# Generated by FakeRAM 2.0 (routing-friendly)
VERSION 5.7 ;
BUSBITCHARS "[]" ;
PROPERTYDEFINITIONS
  MACRO width INTEGER ;
  MACRO depth INTEGER ;
  MACRO banks INTEGER ;
END PROPERTYDEFINITIONS
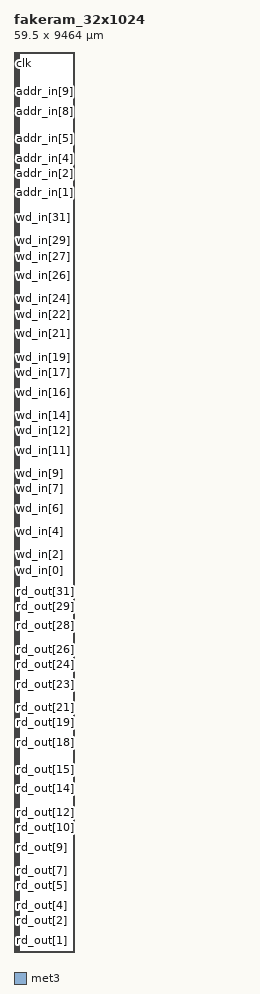
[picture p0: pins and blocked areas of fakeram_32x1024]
MACRO fakeram_32x1024
  PROPERTY width 32 ;
  PROPERTY depth 1024 ;
  PROPERTY banks 1 ;
  FOREIGN fakeram_32x1024 0 0 ;
  SYMMETRY X Y R90 ;
  SIZE 59.500 BY 9464.000 ;
  CLASS BLOCK ;
  PIN rd_out[0]
    DIRECTION OUTPUT ;
    USE SIGNAL ;
    PORT
      LAYER met3 ;
      RECT 1.000 0.680 3.000 1.380 ;
    END
    PORT
      LAYER met3 ;
      RECT 1.000 0.330 4.000 1.730 ;
    END
  END rd_out[0]
  PIN rd_out[1]
    DIRECTION OUTPUT ;
    USE SIGNAL ;
    PORT
      LAYER met3 ;
      RECT 1.000 123.080 3.000 123.780 ;
    END
    PORT
      LAYER met3 ;
      RECT 1.000 122.730 4.000 124.130 ;
    END
  END rd_out[1]
  PIN rd_out[2]
    DIRECTION OUTPUT ;
    USE SIGNAL ;
    PORT
      LAYER met3 ;
      RECT 1.000 245.480 3.000 246.180 ;
    END
    PORT
      LAYER met3 ;
      RECT 1.000 245.130 4.000 246.530 ;
    END
  END rd_out[2]
  PIN rd_out[3]
    DIRECTION OUTPUT ;
    USE SIGNAL ;
    PORT
      LAYER met3 ;
      RECT 1.000 367.880 3.000 368.580 ;
    END
    PORT
      LAYER met3 ;
      RECT 1.000 367.530 4.000 368.930 ;
    END
  END rd_out[3]
  PIN rd_out[4]
    DIRECTION OUTPUT ;
    USE SIGNAL ;
    PORT
      LAYER met3 ;
      RECT 1.000 490.280 3.000 490.980 ;
    END
    PORT
      LAYER met3 ;
      RECT 1.000 489.930 4.000 491.330 ;
    END
  END rd_out[4]
  PIN rd_out[5]
    DIRECTION OUTPUT ;
    USE SIGNAL ;
    PORT
      LAYER met3 ;
      RECT 1.000 612.680 3.000 613.380 ;
    END
    PORT
      LAYER met3 ;
      RECT 1.000 612.330 4.000 613.730 ;
    END
  END rd_out[5]
  PIN rd_out[6]
    DIRECTION OUTPUT ;
    USE SIGNAL ;
    PORT
      LAYER met3 ;
      RECT 1.000 735.080 3.000 735.780 ;
    END
    PORT
      LAYER met3 ;
      RECT 1.000 734.730 4.000 736.130 ;
    END
  END rd_out[6]
  PIN rd_out[7]
    DIRECTION OUTPUT ;
    USE SIGNAL ;
    PORT
      LAYER met3 ;
      RECT 1.000 857.480 3.000 858.180 ;
    END
    PORT
      LAYER met3 ;
      RECT 1.000 857.130 4.000 858.530 ;
    END
  END rd_out[7]
  PIN rd_out[8]
    DIRECTION OUTPUT ;
    USE SIGNAL ;
    PORT
      LAYER met3 ;
      RECT 1.000 979.880 3.000 980.580 ;
    END
    PORT
      LAYER met3 ;
      RECT 1.000 979.530 4.000 980.930 ;
    END
  END rd_out[8]
  PIN rd_out[9]
    DIRECTION OUTPUT ;
    USE SIGNAL ;
    PORT
      LAYER met3 ;
      RECT 1.000 1102.280 3.000 1102.980 ;
    END
    PORT
      LAYER met3 ;
      RECT 1.000 1101.930 4.000 1103.330 ;
    END
  END rd_out[9]
  PIN rd_out[10]
    DIRECTION OUTPUT ;
    USE SIGNAL ;
    PORT
      LAYER met3 ;
      RECT 1.000 1224.680 3.000 1225.380 ;
    END
    PORT
      LAYER met3 ;
      RECT 1.000 1224.330 4.000 1225.730 ;
    END
  END rd_out[10]
  PIN rd_out[11]
    DIRECTION OUTPUT ;
    USE SIGNAL ;
    PORT
      LAYER met3 ;
      RECT 1.000 1347.080 3.000 1347.780 ;
    END
    PORT
      LAYER met3 ;
      RECT 1.000 1346.730 4.000 1348.130 ;
    END
  END rd_out[11]
  PIN rd_out[12]
    DIRECTION OUTPUT ;
    USE SIGNAL ;
    PORT
      LAYER met3 ;
      RECT 1.000 1469.480 3.000 1470.180 ;
    END
    PORT
      LAYER met3 ;
      RECT 1.000 1469.130 4.000 1470.530 ;
    END
  END rd_out[12]
  PIN rd_out[13]
    DIRECTION OUTPUT ;
    USE SIGNAL ;
    PORT
      LAYER met3 ;
      RECT 1.000 1591.880 3.000 1592.580 ;
    END
    PORT
      LAYER met3 ;
      RECT 1.000 1591.530 4.000 1592.930 ;
    END
  END rd_out[13]
  PIN rd_out[14]
    DIRECTION OUTPUT ;
    USE SIGNAL ;
    PORT
      LAYER met3 ;
      RECT 1.000 1714.280 3.000 1714.980 ;
    END
    PORT
      LAYER met3 ;
      RECT 1.000 1713.930 4.000 1715.330 ;
    END
  END rd_out[14]
  PIN rd_out[15]
    DIRECTION OUTPUT ;
    USE SIGNAL ;
    PORT
      LAYER met3 ;
      RECT 1.000 1836.680 3.000 1837.380 ;
    END
    PORT
      LAYER met3 ;
      RECT 1.000 1836.330 4.000 1837.730 ;
    END
  END rd_out[15]
  PIN rd_out[16]
    DIRECTION OUTPUT ;
    USE SIGNAL ;
    PORT
      LAYER met3 ;
      RECT 1.000 1959.080 3.000 1959.780 ;
    END
    PORT
      LAYER met3 ;
      RECT 1.000 1958.730 4.000 1960.130 ;
    END
  END rd_out[16]
  PIN rd_out[17]
    DIRECTION OUTPUT ;
    USE SIGNAL ;
    PORT
      LAYER met3 ;
      RECT 1.000 2081.480 3.000 2082.180 ;
    END
    PORT
      LAYER met3 ;
      RECT 1.000 2081.130 4.000 2082.530 ;
    END
  END rd_out[17]
  PIN rd_out[18]
    DIRECTION OUTPUT ;
    USE SIGNAL ;
    PORT
      LAYER met3 ;
      RECT 1.000 2203.880 3.000 2204.580 ;
    END
    PORT
      LAYER met3 ;
      RECT 1.000 2203.530 4.000 2204.930 ;
    END
  END rd_out[18]
  PIN rd_out[19]
    DIRECTION OUTPUT ;
    USE SIGNAL ;
    PORT
      LAYER met3 ;
      RECT 1.000 2326.280 3.000 2326.980 ;
    END
    PORT
      LAYER met3 ;
      RECT 1.000 2325.930 4.000 2327.330 ;
    END
  END rd_out[19]
  PIN rd_out[20]
    DIRECTION OUTPUT ;
    USE SIGNAL ;
    PORT
      LAYER met3 ;
      RECT 1.000 2448.680 3.000 2449.380 ;
    END
    PORT
      LAYER met3 ;
      RECT 1.000 2448.330 4.000 2449.730 ;
    END
  END rd_out[20]
  PIN rd_out[21]
    DIRECTION OUTPUT ;
    USE SIGNAL ;
    PORT
      LAYER met3 ;
      RECT 1.000 2571.080 3.000 2571.780 ;
    END
    PORT
      LAYER met3 ;
      RECT 1.000 2570.730 4.000 2572.130 ;
    END
  END rd_out[21]
  PIN rd_out[22]
    DIRECTION OUTPUT ;
    USE SIGNAL ;
    PORT
      LAYER met3 ;
      RECT 1.000 2693.480 3.000 2694.180 ;
    END
    PORT
      LAYER met3 ;
      RECT 1.000 2693.130 4.000 2694.530 ;
    END
  END rd_out[22]
  PIN rd_out[23]
    DIRECTION OUTPUT ;
    USE SIGNAL ;
    PORT
      LAYER met3 ;
      RECT 1.000 2815.880 3.000 2816.580 ;
    END
    PORT
      LAYER met3 ;
      RECT 1.000 2815.530 4.000 2816.930 ;
    END
  END rd_out[23]
  PIN rd_out[24]
    DIRECTION OUTPUT ;
    USE SIGNAL ;
    PORT
      LAYER met3 ;
      RECT 1.000 2938.280 3.000 2938.980 ;
    END
    PORT
      LAYER met3 ;
      RECT 1.000 2937.930 4.000 2939.330 ;
    END
  END rd_out[24]
  PIN rd_out[25]
    DIRECTION OUTPUT ;
    USE SIGNAL ;
    PORT
      LAYER met3 ;
      RECT 1.000 3060.680 3.000 3061.380 ;
    END
    PORT
      LAYER met3 ;
      RECT 1.000 3060.330 4.000 3061.730 ;
    END
  END rd_out[25]
  PIN rd_out[26]
    DIRECTION OUTPUT ;
    USE SIGNAL ;
    PORT
      LAYER met3 ;
      RECT 1.000 3183.080 3.000 3183.780 ;
    END
    PORT
      LAYER met3 ;
      RECT 1.000 3182.730 4.000 3184.130 ;
    END
  END rd_out[26]
  PIN rd_out[27]
    DIRECTION OUTPUT ;
    USE SIGNAL ;
    PORT
      LAYER met3 ;
      RECT 1.000 3305.480 3.000 3306.180 ;
    END
    PORT
      LAYER met3 ;
      RECT 1.000 3305.130 4.000 3306.530 ;
    END
  END rd_out[27]
  PIN rd_out[28]
    DIRECTION OUTPUT ;
    USE SIGNAL ;
    PORT
      LAYER met3 ;
      RECT 1.000 3427.880 3.000 3428.580 ;
    END
    PORT
      LAYER met3 ;
      RECT 1.000 3427.530 4.000 3428.930 ;
    END
  END rd_out[28]
  PIN rd_out[29]
    DIRECTION OUTPUT ;
    USE SIGNAL ;
    PORT
      LAYER met3 ;
      RECT 1.000 3550.280 3.000 3550.980 ;
    END
    PORT
      LAYER met3 ;
      RECT 1.000 3549.930 4.000 3551.330 ;
    END
  END rd_out[29]
  PIN rd_out[30]
    DIRECTION OUTPUT ;
    USE SIGNAL ;
    PORT
      LAYER met3 ;
      RECT 1.000 3672.680 3.000 3673.380 ;
    END
    PORT
      LAYER met3 ;
      RECT 1.000 3672.330 4.000 3673.730 ;
    END
  END rd_out[30]
  PIN rd_out[31]
    DIRECTION OUTPUT ;
    USE SIGNAL ;
    PORT
      LAYER met3 ;
      RECT 1.000 3795.080 3.000 3795.780 ;
    END
    PORT
      LAYER met3 ;
      RECT 1.000 3794.730 4.000 3796.130 ;
    END
  END rd_out[31]
  PIN wd_in[0]
    DIRECTION INPUT ;
    USE SIGNAL ;
    PORT
      LAYER met3 ;
      RECT 1.000 3929.720 3.000 3930.420 ;
    END
    PORT
      LAYER met3 ;
      RECT 1.000 3929.370 4.000 3930.770 ;
    END
  END wd_in[0]
  PIN wd_in[1]
    DIRECTION INPUT ;
    USE SIGNAL ;
    PORT
      LAYER met3 ;
      RECT 1.000 4052.120 3.000 4052.820 ;
    END
    PORT
      LAYER met3 ;
      RECT 1.000 4051.770 4.000 4053.170 ;
    END
  END wd_in[1]
  PIN wd_in[2]
    DIRECTION INPUT ;
    USE SIGNAL ;
    PORT
      LAYER met3 ;
      RECT 1.000 4174.520 3.000 4175.220 ;
    END
    PORT
      LAYER met3 ;
      RECT 1.000 4174.170 4.000 4175.570 ;
    END
  END wd_in[2]
  PIN wd_in[3]
    DIRECTION INPUT ;
    USE SIGNAL ;
    PORT
      LAYER met3 ;
      RECT 1.000 4296.920 3.000 4297.620 ;
    END
    PORT
      LAYER met3 ;
      RECT 1.000 4296.570 4.000 4297.970 ;
    END
  END wd_in[3]
  PIN wd_in[4]
    DIRECTION INPUT ;
    USE SIGNAL ;
    PORT
      LAYER met3 ;
      RECT 1.000 4419.320 3.000 4420.020 ;
    END
    PORT
      LAYER met3 ;
      RECT 1.000 4418.970 4.000 4420.370 ;
    END
  END wd_in[4]
  PIN wd_in[5]
    DIRECTION INPUT ;
    USE SIGNAL ;
    PORT
      LAYER met3 ;
      RECT 1.000 4541.720 3.000 4542.420 ;
    END
    PORT
      LAYER met3 ;
      RECT 1.000 4541.370 4.000 4542.770 ;
    END
  END wd_in[5]
  PIN wd_in[6]
    DIRECTION INPUT ;
    USE SIGNAL ;
    PORT
      LAYER met3 ;
      RECT 1.000 4664.120 3.000 4664.820 ;
    END
    PORT
      LAYER met3 ;
      RECT 1.000 4663.770 4.000 4665.170 ;
    END
  END wd_in[6]
  PIN wd_in[7]
    DIRECTION INPUT ;
    USE SIGNAL ;
    PORT
      LAYER met3 ;
      RECT 1.000 4786.520 3.000 4787.220 ;
    END
    PORT
      LAYER met3 ;
      RECT 1.000 4786.170 4.000 4787.570 ;
    END
  END wd_in[7]
  PIN wd_in[8]
    DIRECTION INPUT ;
    USE SIGNAL ;
    PORT
      LAYER met3 ;
      RECT 1.000 4908.920 3.000 4909.620 ;
    END
    PORT
      LAYER met3 ;
      RECT 1.000 4908.570 4.000 4909.970 ;
    END
  END wd_in[8]
  PIN wd_in[9]
    DIRECTION INPUT ;
    USE SIGNAL ;
    PORT
      LAYER met3 ;
      RECT 1.000 5031.320 3.000 5032.020 ;
    END
    PORT
      LAYER met3 ;
      RECT 1.000 5030.970 4.000 5032.370 ;
    END
  END wd_in[9]
  PIN wd_in[10]
    DIRECTION INPUT ;
    USE SIGNAL ;
    PORT
      LAYER met3 ;
      RECT 1.000 5153.720 3.000 5154.420 ;
    END
    PORT
      LAYER met3 ;
      RECT 1.000 5153.370 4.000 5154.770 ;
    END
  END wd_in[10]
  PIN wd_in[11]
    DIRECTION INPUT ;
    USE SIGNAL ;
    PORT
      LAYER met3 ;
      RECT 1.000 5276.120 3.000 5276.820 ;
    END
    PORT
      LAYER met3 ;
      RECT 1.000 5275.770 4.000 5277.170 ;
    END
  END wd_in[11]
  PIN wd_in[12]
    DIRECTION INPUT ;
    USE SIGNAL ;
    PORT
      LAYER met3 ;
      RECT 1.000 5398.520 3.000 5399.220 ;
    END
    PORT
      LAYER met3 ;
      RECT 1.000 5398.170 4.000 5399.570 ;
    END
  END wd_in[12]
  PIN wd_in[13]
    DIRECTION INPUT ;
    USE SIGNAL ;
    PORT
      LAYER met3 ;
      RECT 1.000 5520.920 3.000 5521.620 ;
    END
    PORT
      LAYER met3 ;
      RECT 1.000 5520.570 4.000 5521.970 ;
    END
  END wd_in[13]
  PIN wd_in[14]
    DIRECTION INPUT ;
    USE SIGNAL ;
    PORT
      LAYER met3 ;
      RECT 1.000 5643.320 3.000 5644.020 ;
    END
    PORT
      LAYER met3 ;
      RECT 1.000 5642.970 4.000 5644.370 ;
    END
  END wd_in[14]
  PIN wd_in[15]
    DIRECTION INPUT ;
    USE SIGNAL ;
    PORT
      LAYER met3 ;
      RECT 1.000 5765.720 3.000 5766.420 ;
    END
    PORT
      LAYER met3 ;
      RECT 1.000 5765.370 4.000 5766.770 ;
    END
  END wd_in[15]
  PIN wd_in[16]
    DIRECTION INPUT ;
    USE SIGNAL ;
    PORT
      LAYER met3 ;
      RECT 1.000 5888.120 3.000 5888.820 ;
    END
    PORT
      LAYER met3 ;
      RECT 1.000 5887.770 4.000 5889.170 ;
    END
  END wd_in[16]
  PIN wd_in[17]
    DIRECTION INPUT ;
    USE SIGNAL ;
    PORT
      LAYER met3 ;
      RECT 1.000 6010.520 3.000 6011.220 ;
    END
    PORT
      LAYER met3 ;
      RECT 1.000 6010.170 4.000 6011.570 ;
    END
  END wd_in[17]
  PIN wd_in[18]
    DIRECTION INPUT ;
    USE SIGNAL ;
    PORT
      LAYER met3 ;
      RECT 1.000 6132.920 3.000 6133.620 ;
    END
    PORT
      LAYER met3 ;
      RECT 1.000 6132.570 4.000 6133.970 ;
    END
  END wd_in[18]
  PIN wd_in[19]
    DIRECTION INPUT ;
    USE SIGNAL ;
    PORT
      LAYER met3 ;
      RECT 1.000 6255.320 3.000 6256.020 ;
    END
    PORT
      LAYER met3 ;
      RECT 1.000 6254.970 4.000 6256.370 ;
    END
  END wd_in[19]
  PIN wd_in[20]
    DIRECTION INPUT ;
    USE SIGNAL ;
    PORT
      LAYER met3 ;
      RECT 1.000 6377.720 3.000 6378.420 ;
    END
    PORT
      LAYER met3 ;
      RECT 1.000 6377.370 4.000 6378.770 ;
    END
  END wd_in[20]
  PIN wd_in[21]
    DIRECTION INPUT ;
    USE SIGNAL ;
    PORT
      LAYER met3 ;
      RECT 1.000 6500.120 3.000 6500.820 ;
    END
    PORT
      LAYER met3 ;
      RECT 1.000 6499.770 4.000 6501.170 ;
    END
  END wd_in[21]
  PIN wd_in[22]
    DIRECTION INPUT ;
    USE SIGNAL ;
    PORT
      LAYER met3 ;
      RECT 1.000 6622.520 3.000 6623.220 ;
    END
    PORT
      LAYER met3 ;
      RECT 1.000 6622.170 4.000 6623.570 ;
    END
  END wd_in[22]
  PIN wd_in[23]
    DIRECTION INPUT ;
    USE SIGNAL ;
    PORT
      LAYER met3 ;
      RECT 1.000 6744.920 3.000 6745.620 ;
    END
    PORT
      LAYER met3 ;
      RECT 1.000 6744.570 4.000 6745.970 ;
    END
  END wd_in[23]
  PIN wd_in[24]
    DIRECTION INPUT ;
    USE SIGNAL ;
    PORT
      LAYER met3 ;
      RECT 1.000 6867.320 3.000 6868.020 ;
    END
    PORT
      LAYER met3 ;
      RECT 1.000 6866.970 4.000 6868.370 ;
    END
  END wd_in[24]
  PIN wd_in[25]
    DIRECTION INPUT ;
    USE SIGNAL ;
    PORT
      LAYER met3 ;
      RECT 1.000 6989.720 3.000 6990.420 ;
    END
    PORT
      LAYER met3 ;
      RECT 1.000 6989.370 4.000 6990.770 ;
    END
  END wd_in[25]
  PIN wd_in[26]
    DIRECTION INPUT ;
    USE SIGNAL ;
    PORT
      LAYER met3 ;
      RECT 1.000 7112.120 3.000 7112.820 ;
    END
    PORT
      LAYER met3 ;
      RECT 1.000 7111.770 4.000 7113.170 ;
    END
  END wd_in[26]
  PIN wd_in[27]
    DIRECTION INPUT ;
    USE SIGNAL ;
    PORT
      LAYER met3 ;
      RECT 1.000 7234.520 3.000 7235.220 ;
    END
    PORT
      LAYER met3 ;
      RECT 1.000 7234.170 4.000 7235.570 ;
    END
  END wd_in[27]
  PIN wd_in[28]
    DIRECTION INPUT ;
    USE SIGNAL ;
    PORT
      LAYER met3 ;
      RECT 1.000 7356.920 3.000 7357.620 ;
    END
    PORT
      LAYER met3 ;
      RECT 1.000 7356.570 4.000 7357.970 ;
    END
  END wd_in[28]
  PIN wd_in[29]
    DIRECTION INPUT ;
    USE SIGNAL ;
    PORT
      LAYER met3 ;
      RECT 1.000 7479.320 3.000 7480.020 ;
    END
    PORT
      LAYER met3 ;
      RECT 1.000 7478.970 4.000 7480.370 ;
    END
  END wd_in[29]
  PIN wd_in[30]
    DIRECTION INPUT ;
    USE SIGNAL ;
    PORT
      LAYER met3 ;
      RECT 1.000 7601.720 3.000 7602.420 ;
    END
    PORT
      LAYER met3 ;
      RECT 1.000 7601.370 4.000 7602.770 ;
    END
  END wd_in[30]
  PIN wd_in[31]
    DIRECTION INPUT ;
    USE SIGNAL ;
    PORT
      LAYER met3 ;
      RECT 1.000 7724.120 3.000 7724.820 ;
    END
    PORT
      LAYER met3 ;
      RECT 1.000 7723.770 4.000 7725.170 ;
    END
  END wd_in[31]
  PIN addr_in[0]
    DIRECTION INPUT ;
    USE SIGNAL ;
    PORT
      LAYER met3 ;
      RECT 1.000 7858.760 3.000 7859.460 ;
    END
    PORT
      LAYER met3 ;
      RECT 1.000 7858.410 4.000 7859.810 ;
    END
  END addr_in[0]
  PIN addr_in[1]
    DIRECTION INPUT ;
    USE SIGNAL ;
    PORT
      LAYER met3 ;
      RECT 1.000 7981.160 3.000 7981.860 ;
    END
    PORT
      LAYER met3 ;
      RECT 1.000 7980.810 4.000 7982.210 ;
    END
  END addr_in[1]
  PIN addr_in[2]
    DIRECTION INPUT ;
    USE SIGNAL ;
    PORT
      LAYER met3 ;
      RECT 1.000 8103.560 3.000 8104.260 ;
    END
    PORT
      LAYER met3 ;
      RECT 1.000 8103.210 4.000 8104.610 ;
    END
  END addr_in[2]
  PIN addr_in[3]
    DIRECTION INPUT ;
    USE SIGNAL ;
    PORT
      LAYER met3 ;
      RECT 1.000 8225.960 3.000 8226.660 ;
    END
    PORT
      LAYER met3 ;
      RECT 1.000 8225.610 4.000 8227.010 ;
    END
  END addr_in[3]
  PIN addr_in[4]
    DIRECTION INPUT ;
    USE SIGNAL ;
    PORT
      LAYER met3 ;
      RECT 1.000 8348.360 3.000 8349.060 ;
    END
    PORT
      LAYER met3 ;
      RECT 1.000 8348.010 4.000 8349.410 ;
    END
  END addr_in[4]
  PIN addr_in[5]
    DIRECTION INPUT ;
    USE SIGNAL ;
    PORT
      LAYER met3 ;
      RECT 1.000 8470.760 3.000 8471.460 ;
    END
    PORT
      LAYER met3 ;
      RECT 1.000 8470.410 4.000 8471.810 ;
    END
  END addr_in[5]
  PIN addr_in[6]
    DIRECTION INPUT ;
    USE SIGNAL ;
    PORT
      LAYER met3 ;
      RECT 1.000 8593.160 3.000 8593.860 ;
    END
    PORT
      LAYER met3 ;
      RECT 1.000 8592.810 4.000 8594.210 ;
    END
  END addr_in[6]
  PIN addr_in[7]
    DIRECTION INPUT ;
    USE SIGNAL ;
    PORT
      LAYER met3 ;
      RECT 1.000 8715.560 3.000 8716.260 ;
    END
    PORT
      LAYER met3 ;
      RECT 1.000 8715.210 4.000 8716.610 ;
    END
  END addr_in[7]
  PIN addr_in[8]
    DIRECTION INPUT ;
    USE SIGNAL ;
    PORT
      LAYER met3 ;
      RECT 1.000 8837.960 3.000 8838.660 ;
    END
    PORT
      LAYER met3 ;
      RECT 1.000 8837.610 4.000 8839.010 ;
    END
  END addr_in[8]
  PIN addr_in[9]
    DIRECTION INPUT ;
    USE SIGNAL ;
    PORT
      LAYER met3 ;
      RECT 1.000 8960.360 3.000 8961.060 ;
    END
    PORT
      LAYER met3 ;
      RECT 1.000 8960.010 4.000 8961.410 ;
    END
  END addr_in[9]
  PIN we_in
    DIRECTION INPUT ;
    USE SIGNAL ;
    PORT
      LAYER met3 ;
      RECT 1.000 9095.000 3.000 9095.700 ;
    END
    PORT
      LAYER met3 ;
      RECT 1.000 9094.650 4.000 9096.050 ;
    END
  END we_in
  PIN ce_in
    DIRECTION INPUT ;
    USE SIGNAL ;
    PORT
      LAYER met3 ;
      RECT 1.000 9217.400 3.000 9218.100 ;
    END
    PORT
      LAYER met3 ;
      RECT 1.000 9217.050 4.000 9218.450 ;
    END
  END ce_in
  PIN clk
    DIRECTION INPUT ;
    USE SIGNAL ;
    PORT
      LAYER met3 ;
      RECT 1.000 9339.800 3.000 9340.500 ;
    END
    PORT
      LAYER met3 ;
      RECT 1.000 9339.450 4.000 9340.850 ;
    END
  END clk
  PIN VSS
    DIRECTION INOUT ;
    USE GROUND ;
    PORT
      LAYER met3 ;
      RECT 0.680 -0.720 58.820 2.080 ;
      RECT 0.680 10.160 58.820 12.960 ;
      RECT 0.680 21.040 58.820 23.840 ;
      RECT 0.680 31.920 58.820 34.720 ;
      RECT 0.680 42.800 58.820 45.600 ;
      RECT 0.680 53.680 58.820 56.480 ;
      RECT 0.680 64.560 58.820 67.360 ;
      RECT 0.680 75.440 58.820 78.240 ;
      RECT 0.680 86.320 58.820 89.120 ;
      RECT 0.680 97.200 58.820 100.000 ;
      RECT 0.680 108.080 58.820 110.880 ;
      RECT 0.680 118.960 58.820 121.760 ;
      RECT 0.680 129.840 58.820 132.640 ;
      RECT 0.680 140.720 58.820 143.520 ;
      RECT 0.680 151.600 58.820 154.400 ;
      RECT 0.680 162.480 58.820 165.280 ;
      RECT 0.680 173.360 58.820 176.160 ;
      RECT 0.680 184.240 58.820 187.040 ;
      RECT 0.680 195.120 58.820 197.920 ;
      RECT 0.680 206.000 58.820 208.800 ;
      RECT 0.680 216.880 58.820 219.680 ;
      RECT 0.680 227.760 58.820 230.560 ;
      RECT 0.680 238.640 58.820 241.440 ;
      RECT 0.680 249.520 58.820 252.320 ;
      RECT 0.680 260.400 58.820 263.200 ;
      RECT 0.680 271.280 58.820 274.080 ;
      RECT 0.680 282.160 58.820 284.960 ;
      RECT 0.680 293.040 58.820 295.840 ;
      RECT 0.680 303.920 58.820 306.720 ;
      RECT 0.680 314.800 58.820 317.600 ;
      RECT 0.680 325.680 58.820 328.480 ;
      RECT 0.680 336.560 58.820 339.360 ;
      RECT 0.680 347.440 58.820 350.240 ;
      RECT 0.680 358.320 58.820 361.120 ;
      RECT 0.680 369.200 58.820 372.000 ;
      RECT 0.680 380.080 58.820 382.880 ;
      RECT 0.680 390.960 58.820 393.760 ;
      RECT 0.680 401.840 58.820 404.640 ;
      RECT 0.680 412.720 58.820 415.520 ;
      RECT 0.680 423.600 58.820 426.400 ;
      RECT 0.680 434.480 58.820 437.280 ;
      RECT 0.680 445.360 58.820 448.160 ;
      RECT 0.680 456.240 58.820 459.040 ;
      RECT 0.680 467.120 58.820 469.920 ;
      RECT 0.680 478.000 58.820 480.800 ;
      RECT 0.680 488.880 58.820 491.680 ;
      RECT 0.680 499.760 58.820 502.560 ;
      RECT 0.680 510.640 58.820 513.440 ;
      RECT 0.680 521.520 58.820 524.320 ;
      RECT 0.680 532.400 58.820 535.200 ;
      RECT 0.680 543.280 58.820 546.080 ;
      RECT 0.680 554.160 58.820 556.960 ;
      RECT 0.680 565.040 58.820 567.840 ;
      RECT 0.680 575.920 58.820 578.720 ;
      RECT 0.680 586.800 58.820 589.600 ;
      RECT 0.680 597.680 58.820 600.480 ;
      RECT 0.680 608.560 58.820 611.360 ;
      RECT 0.680 619.440 58.820 622.240 ;
      RECT 0.680 630.320 58.820 633.120 ;
      RECT 0.680 641.200 58.820 644.000 ;
      RECT 0.680 652.080 58.820 654.880 ;
      RECT 0.680 662.960 58.820 665.760 ;
      RECT 0.680 673.840 58.820 676.640 ;
      RECT 0.680 684.720 58.820 687.520 ;
      RECT 0.680 695.600 58.820 698.400 ;
      RECT 0.680 706.480 58.820 709.280 ;
      RECT 0.680 717.360 58.820 720.160 ;
      RECT 0.680 728.240 58.820 731.040 ;
      RECT 0.680 739.120 58.820 741.920 ;
      RECT 0.680 750.000 58.820 752.800 ;
      RECT 0.680 760.880 58.820 763.680 ;
      RECT 0.680 771.760 58.820 774.560 ;
      RECT 0.680 782.640 58.820 785.440 ;
      RECT 0.680 793.520 58.820 796.320 ;
      RECT 0.680 804.400 58.820 807.200 ;
      RECT 0.680 815.280 58.820 818.080 ;
      RECT 0.680 826.160 58.820 828.960 ;
      RECT 0.680 837.040 58.820 839.840 ;
      RECT 0.680 847.920 58.820 850.720 ;
      RECT 0.680 858.800 58.820 861.600 ;
      RECT 0.680 869.680 58.820 872.480 ;
      RECT 0.680 880.560 58.820 883.360 ;
      RECT 0.680 891.440 58.820 894.240 ;
      RECT 0.680 902.320 58.820 905.120 ;
      RECT 0.680 913.200 58.820 916.000 ;
      RECT 0.680 924.080 58.820 926.880 ;
      RECT 0.680 934.960 58.820 937.760 ;
      RECT 0.680 945.840 58.820 948.640 ;
      RECT 0.680 956.720 58.820 959.520 ;
      RECT 0.680 967.600 58.820 970.400 ;
      RECT 0.680 978.480 58.820 981.280 ;
      RECT 0.680 989.360 58.820 992.160 ;
      RECT 0.680 1000.240 58.820 1003.040 ;
      RECT 0.680 1011.120 58.820 1013.920 ;
      RECT 0.680 1022.000 58.820 1024.800 ;
      RECT 0.680 1032.880 58.820 1035.680 ;
      RECT 0.680 1043.760 58.820 1046.560 ;
      RECT 0.680 1054.640 58.820 1057.440 ;
      RECT 0.680 1065.520 58.820 1068.320 ;
      RECT 0.680 1076.400 58.820 1079.200 ;
      RECT 0.680 1087.280 58.820 1090.080 ;
      RECT 0.680 1098.160 58.820 1100.960 ;
      RECT 0.680 1109.040 58.820 1111.840 ;
      RECT 0.680 1119.920 58.820 1122.720 ;
      RECT 0.680 1130.800 58.820 1133.600 ;
      RECT 0.680 1141.680 58.820 1144.480 ;
      RECT 0.680 1152.560 58.820 1155.360 ;
      RECT 0.680 1163.440 58.820 1166.240 ;
      RECT 0.680 1174.320 58.820 1177.120 ;
      RECT 0.680 1185.200 58.820 1188.000 ;
      RECT 0.680 1196.080 58.820 1198.880 ;
      RECT 0.680 1206.960 58.820 1209.760 ;
      RECT 0.680 1217.840 58.820 1220.640 ;
      RECT 0.680 1228.720 58.820 1231.520 ;
      RECT 0.680 1239.600 58.820 1242.400 ;
      RECT 0.680 1250.480 58.820 1253.280 ;
      RECT 0.680 1261.360 58.820 1264.160 ;
      RECT 0.680 1272.240 58.820 1275.040 ;
      RECT 0.680 1283.120 58.820 1285.920 ;
      RECT 0.680 1294.000 58.820 1296.800 ;
      RECT 0.680 1304.880 58.820 1307.680 ;
      RECT 0.680 1315.760 58.820 1318.560 ;
      RECT 0.680 1326.640 58.820 1329.440 ;
      RECT 0.680 1337.520 58.820 1340.320 ;
      RECT 0.680 1348.400 58.820 1351.200 ;
      RECT 0.680 1359.280 58.820 1362.080 ;
      RECT 0.680 1370.160 58.820 1372.960 ;
      RECT 0.680 1381.040 58.820 1383.840 ;
      RECT 0.680 1391.920 58.820 1394.720 ;
      RECT 0.680 1402.800 58.820 1405.600 ;
      RECT 0.680 1413.680 58.820 1416.480 ;
      RECT 0.680 1424.560 58.820 1427.360 ;
      RECT 0.680 1435.440 58.820 1438.240 ;
      RECT 0.680 1446.320 58.820 1449.120 ;
      RECT 0.680 1457.200 58.820 1460.000 ;
      RECT 0.680 1468.080 58.820 1470.880 ;
      RECT 0.680 1478.960 58.820 1481.760 ;
      RECT 0.680 1489.840 58.820 1492.640 ;
      RECT 0.680 1500.720 58.820 1503.520 ;
      RECT 0.680 1511.600 58.820 1514.400 ;
      RECT 0.680 1522.480 58.820 1525.280 ;
      RECT 0.680 1533.360 58.820 1536.160 ;
      RECT 0.680 1544.240 58.820 1547.040 ;
      RECT 0.680 1555.120 58.820 1557.920 ;
      RECT 0.680 1566.000 58.820 1568.800 ;
      RECT 0.680 1576.880 58.820 1579.680 ;
      RECT 0.680 1587.760 58.820 1590.560 ;
      RECT 0.680 1598.640 58.820 1601.440 ;
      RECT 0.680 1609.520 58.820 1612.320 ;
      RECT 0.680 1620.400 58.820 1623.200 ;
      RECT 0.680 1631.280 58.820 1634.080 ;
      RECT 0.680 1642.160 58.820 1644.960 ;
      RECT 0.680 1653.040 58.820 1655.840 ;
      RECT 0.680 1663.920 58.820 1666.720 ;
      RECT 0.680 1674.800 58.820 1677.600 ;
      RECT 0.680 1685.680 58.820 1688.480 ;
      RECT 0.680 1696.560 58.820 1699.360 ;
      RECT 0.680 1707.440 58.820 1710.240 ;
      RECT 0.680 1718.320 58.820 1721.120 ;
      RECT 0.680 1729.200 58.820 1732.000 ;
      RECT 0.680 1740.080 58.820 1742.880 ;
      RECT 0.680 1750.960 58.820 1753.760 ;
      RECT 0.680 1761.840 58.820 1764.640 ;
      RECT 0.680 1772.720 58.820 1775.520 ;
      RECT 0.680 1783.600 58.820 1786.400 ;
      RECT 0.680 1794.480 58.820 1797.280 ;
      RECT 0.680 1805.360 58.820 1808.160 ;
      RECT 0.680 1816.240 58.820 1819.040 ;
      RECT 0.680 1827.120 58.820 1829.920 ;
      RECT 0.680 1838.000 58.820 1840.800 ;
      RECT 0.680 1848.880 58.820 1851.680 ;
      RECT 0.680 1859.760 58.820 1862.560 ;
      RECT 0.680 1870.640 58.820 1873.440 ;
      RECT 0.680 1881.520 58.820 1884.320 ;
      RECT 0.680 1892.400 58.820 1895.200 ;
      RECT 0.680 1903.280 58.820 1906.080 ;
      RECT 0.680 1914.160 58.820 1916.960 ;
      RECT 0.680 1925.040 58.820 1927.840 ;
      RECT 0.680 1935.920 58.820 1938.720 ;
      RECT 0.680 1946.800 58.820 1949.600 ;
      RECT 0.680 1957.680 58.820 1960.480 ;
      RECT 0.680 1968.560 58.820 1971.360 ;
      RECT 0.680 1979.440 58.820 1982.240 ;
      RECT 0.680 1990.320 58.820 1993.120 ;
      RECT 0.680 2001.200 58.820 2004.000 ;
      RECT 0.680 2012.080 58.820 2014.880 ;
      RECT 0.680 2022.960 58.820 2025.760 ;
      RECT 0.680 2033.840 58.820 2036.640 ;
      RECT 0.680 2044.720 58.820 2047.520 ;
      RECT 0.680 2055.600 58.820 2058.400 ;
      RECT 0.680 2066.480 58.820 2069.280 ;
      RECT 0.680 2077.360 58.820 2080.160 ;
      RECT 0.680 2088.240 58.820 2091.040 ;
      RECT 0.680 2099.120 58.820 2101.920 ;
      RECT 0.680 2110.000 58.820 2112.800 ;
      RECT 0.680 2120.880 58.820 2123.680 ;
      RECT 0.680 2131.760 58.820 2134.560 ;
      RECT 0.680 2142.640 58.820 2145.440 ;
      RECT 0.680 2153.520 58.820 2156.320 ;
      RECT 0.680 2164.400 58.820 2167.200 ;
      RECT 0.680 2175.280 58.820 2178.080 ;
      RECT 0.680 2186.160 58.820 2188.960 ;
      RECT 0.680 2197.040 58.820 2199.840 ;
      RECT 0.680 2207.920 58.820 2210.720 ;
      RECT 0.680 2218.800 58.820 2221.600 ;
      RECT 0.680 2229.680 58.820 2232.480 ;
      RECT 0.680 2240.560 58.820 2243.360 ;
      RECT 0.680 2251.440 58.820 2254.240 ;
      RECT 0.680 2262.320 58.820 2265.120 ;
      RECT 0.680 2273.200 58.820 2276.000 ;
      RECT 0.680 2284.080 58.820 2286.880 ;
      RECT 0.680 2294.960 58.820 2297.760 ;
      RECT 0.680 2305.840 58.820 2308.640 ;
      RECT 0.680 2316.720 58.820 2319.520 ;
      RECT 0.680 2327.600 58.820 2330.400 ;
      RECT 0.680 2338.480 58.820 2341.280 ;
      RECT 0.680 2349.360 58.820 2352.160 ;
      RECT 0.680 2360.240 58.820 2363.040 ;
      RECT 0.680 2371.120 58.820 2373.920 ;
      RECT 0.680 2382.000 58.820 2384.800 ;
      RECT 0.680 2392.880 58.820 2395.680 ;
      RECT 0.680 2403.760 58.820 2406.560 ;
      RECT 0.680 2414.640 58.820 2417.440 ;
      RECT 0.680 2425.520 58.820 2428.320 ;
      RECT 0.680 2436.400 58.820 2439.200 ;
      RECT 0.680 2447.280 58.820 2450.080 ;
      RECT 0.680 2458.160 58.820 2460.960 ;
      RECT 0.680 2469.040 58.820 2471.840 ;
      RECT 0.680 2479.920 58.820 2482.720 ;
      RECT 0.680 2490.800 58.820 2493.600 ;
      RECT 0.680 2501.680 58.820 2504.480 ;
      RECT 0.680 2512.560 58.820 2515.360 ;
      RECT 0.680 2523.440 58.820 2526.240 ;
      RECT 0.680 2534.320 58.820 2537.120 ;
      RECT 0.680 2545.200 58.820 2548.000 ;
      RECT 0.680 2556.080 58.820 2558.880 ;
      RECT 0.680 2566.960 58.820 2569.760 ;
      RECT 0.680 2577.840 58.820 2580.640 ;
      RECT 0.680 2588.720 58.820 2591.520 ;
      RECT 0.680 2599.600 58.820 2602.400 ;
      RECT 0.680 2610.480 58.820 2613.280 ;
      RECT 0.680 2621.360 58.820 2624.160 ;
      RECT 0.680 2632.240 58.820 2635.040 ;
      RECT 0.680 2643.120 58.820 2645.920 ;
      RECT 0.680 2654.000 58.820 2656.800 ;
      RECT 0.680 2664.880 58.820 2667.680 ;
      RECT 0.680 2675.760 58.820 2678.560 ;
      RECT 0.680 2686.640 58.820 2689.440 ;
      RECT 0.680 2697.520 58.820 2700.320 ;
      RECT 0.680 2708.400 58.820 2711.200 ;
      RECT 0.680 2719.280 58.820 2722.080 ;
      RECT 0.680 2730.160 58.820 2732.960 ;
      RECT 0.680 2741.040 58.820 2743.840 ;
      RECT 0.680 2751.920 58.820 2754.720 ;
      RECT 0.680 2762.800 58.820 2765.600 ;
      RECT 0.680 2773.680 58.820 2776.480 ;
      RECT 0.680 2784.560 58.820 2787.360 ;
      RECT 0.680 2795.440 58.820 2798.240 ;
      RECT 0.680 2806.320 58.820 2809.120 ;
      RECT 0.680 2817.200 58.820 2820.000 ;
      RECT 0.680 2828.080 58.820 2830.880 ;
      RECT 0.680 2838.960 58.820 2841.760 ;
      RECT 0.680 2849.840 58.820 2852.640 ;
      RECT 0.680 2860.720 58.820 2863.520 ;
      RECT 0.680 2871.600 58.820 2874.400 ;
      RECT 0.680 2882.480 58.820 2885.280 ;
      RECT 0.680 2893.360 58.820 2896.160 ;
      RECT 0.680 2904.240 58.820 2907.040 ;
      RECT 0.680 2915.120 58.820 2917.920 ;
      RECT 0.680 2926.000 58.820 2928.800 ;
      RECT 0.680 2936.880 58.820 2939.680 ;
      RECT 0.680 2947.760 58.820 2950.560 ;
      RECT 0.680 2958.640 58.820 2961.440 ;
      RECT 0.680 2969.520 58.820 2972.320 ;
      RECT 0.680 2980.400 58.820 2983.200 ;
      RECT 0.680 2991.280 58.820 2994.080 ;
      RECT 0.680 3002.160 58.820 3004.960 ;
      RECT 0.680 3013.040 58.820 3015.840 ;
      RECT 0.680 3023.920 58.820 3026.720 ;
      RECT 0.680 3034.800 58.820 3037.600 ;
      RECT 0.680 3045.680 58.820 3048.480 ;
      RECT 0.680 3056.560 58.820 3059.360 ;
      RECT 0.680 3067.440 58.820 3070.240 ;
      RECT 0.680 3078.320 58.820 3081.120 ;
      RECT 0.680 3089.200 58.820 3092.000 ;
      RECT 0.680 3100.080 58.820 3102.880 ;
      RECT 0.680 3110.960 58.820 3113.760 ;
      RECT 0.680 3121.840 58.820 3124.640 ;
      RECT 0.680 3132.720 58.820 3135.520 ;
      RECT 0.680 3143.600 58.820 3146.400 ;
      RECT 0.680 3154.480 58.820 3157.280 ;
      RECT 0.680 3165.360 58.820 3168.160 ;
      RECT 0.680 3176.240 58.820 3179.040 ;
      RECT 0.680 3187.120 58.820 3189.920 ;
      RECT 0.680 3198.000 58.820 3200.800 ;
      RECT 0.680 3208.880 58.820 3211.680 ;
      RECT 0.680 3219.760 58.820 3222.560 ;
      RECT 0.680 3230.640 58.820 3233.440 ;
      RECT 0.680 3241.520 58.820 3244.320 ;
      RECT 0.680 3252.400 58.820 3255.200 ;
      RECT 0.680 3263.280 58.820 3266.080 ;
      RECT 0.680 3274.160 58.820 3276.960 ;
      RECT 0.680 3285.040 58.820 3287.840 ;
      RECT 0.680 3295.920 58.820 3298.720 ;
      RECT 0.680 3306.800 58.820 3309.600 ;
      RECT 0.680 3317.680 58.820 3320.480 ;
      RECT 0.680 3328.560 58.820 3331.360 ;
      RECT 0.680 3339.440 58.820 3342.240 ;
      RECT 0.680 3350.320 58.820 3353.120 ;
      RECT 0.680 3361.200 58.820 3364.000 ;
      RECT 0.680 3372.080 58.820 3374.880 ;
      RECT 0.680 3382.960 58.820 3385.760 ;
      RECT 0.680 3393.840 58.820 3396.640 ;
      RECT 0.680 3404.720 58.820 3407.520 ;
      RECT 0.680 3415.600 58.820 3418.400 ;
      RECT 0.680 3426.480 58.820 3429.280 ;
      RECT 0.680 3437.360 58.820 3440.160 ;
      RECT 0.680 3448.240 58.820 3451.040 ;
      RECT 0.680 3459.120 58.820 3461.920 ;
      RECT 0.680 3470.000 58.820 3472.800 ;
      RECT 0.680 3480.880 58.820 3483.680 ;
      RECT 0.680 3491.760 58.820 3494.560 ;
      RECT 0.680 3502.640 58.820 3505.440 ;
      RECT 0.680 3513.520 58.820 3516.320 ;
      RECT 0.680 3524.400 58.820 3527.200 ;
      RECT 0.680 3535.280 58.820 3538.080 ;
      RECT 0.680 3546.160 58.820 3548.960 ;
      RECT 0.680 3557.040 58.820 3559.840 ;
      RECT 0.680 3567.920 58.820 3570.720 ;
      RECT 0.680 3578.800 58.820 3581.600 ;
      RECT 0.680 3589.680 58.820 3592.480 ;
      RECT 0.680 3600.560 58.820 3603.360 ;
      RECT 0.680 3611.440 58.820 3614.240 ;
      RECT 0.680 3622.320 58.820 3625.120 ;
      RECT 0.680 3633.200 58.820 3636.000 ;
      RECT 0.680 3644.080 58.820 3646.880 ;
      RECT 0.680 3654.960 58.820 3657.760 ;
      RECT 0.680 3665.840 58.820 3668.640 ;
      RECT 0.680 3676.720 58.820 3679.520 ;
      RECT 0.680 3687.600 58.820 3690.400 ;
      RECT 0.680 3698.480 58.820 3701.280 ;
      RECT 0.680 3709.360 58.820 3712.160 ;
      RECT 0.680 3720.240 58.820 3723.040 ;
      RECT 0.680 3731.120 58.820 3733.920 ;
      RECT 0.680 3742.000 58.820 3744.800 ;
      RECT 0.680 3752.880 58.820 3755.680 ;
      RECT 0.680 3763.760 58.820 3766.560 ;
      RECT 0.680 3774.640 58.820 3777.440 ;
      RECT 0.680 3785.520 58.820 3788.320 ;
      RECT 0.680 3796.400 58.820 3799.200 ;
      RECT 0.680 3807.280 58.820 3810.080 ;
      RECT 0.680 3818.160 58.820 3820.960 ;
      RECT 0.680 3829.040 58.820 3831.840 ;
      RECT 0.680 3839.920 58.820 3842.720 ;
      RECT 0.680 3850.800 58.820 3853.600 ;
      RECT 0.680 3861.680 58.820 3864.480 ;
      RECT 0.680 3872.560 58.820 3875.360 ;
      RECT 0.680 3883.440 58.820 3886.240 ;
      RECT 0.680 3894.320 58.820 3897.120 ;
      RECT 0.680 3905.200 58.820 3908.000 ;
      RECT 0.680 3916.080 58.820 3918.880 ;
      RECT 0.680 3926.960 58.820 3929.760 ;
      RECT 0.680 3937.840 58.820 3940.640 ;
      RECT 0.680 3948.720 58.820 3951.520 ;
      RECT 0.680 3959.600 58.820 3962.400 ;
      RECT 0.680 3970.480 58.820 3973.280 ;
      RECT 0.680 3981.360 58.820 3984.160 ;
      RECT 0.680 3992.240 58.820 3995.040 ;
      RECT 0.680 4003.120 58.820 4005.920 ;
      RECT 0.680 4014.000 58.820 4016.800 ;
      RECT 0.680 4024.880 58.820 4027.680 ;
      RECT 0.680 4035.760 58.820 4038.560 ;
      RECT 0.680 4046.640 58.820 4049.440 ;
      RECT 0.680 4057.520 58.820 4060.320 ;
      RECT 0.680 4068.400 58.820 4071.200 ;
      RECT 0.680 4079.280 58.820 4082.080 ;
      RECT 0.680 4090.160 58.820 4092.960 ;
      RECT 0.680 4101.040 58.820 4103.840 ;
      RECT 0.680 4111.920 58.820 4114.720 ;
      RECT 0.680 4122.800 58.820 4125.600 ;
      RECT 0.680 4133.680 58.820 4136.480 ;
      RECT 0.680 4144.560 58.820 4147.360 ;
      RECT 0.680 4155.440 58.820 4158.240 ;
      RECT 0.680 4166.320 58.820 4169.120 ;
      RECT 0.680 4177.200 58.820 4180.000 ;
      RECT 0.680 4188.080 58.820 4190.880 ;
      RECT 0.680 4198.960 58.820 4201.760 ;
      RECT 0.680 4209.840 58.820 4212.640 ;
      RECT 0.680 4220.720 58.820 4223.520 ;
      RECT 0.680 4231.600 58.820 4234.400 ;
      RECT 0.680 4242.480 58.820 4245.280 ;
      RECT 0.680 4253.360 58.820 4256.160 ;
      RECT 0.680 4264.240 58.820 4267.040 ;
      RECT 0.680 4275.120 58.820 4277.920 ;
      RECT 0.680 4286.000 58.820 4288.800 ;
      RECT 0.680 4296.880 58.820 4299.680 ;
      RECT 0.680 4307.760 58.820 4310.560 ;
      RECT 0.680 4318.640 58.820 4321.440 ;
      RECT 0.680 4329.520 58.820 4332.320 ;
      RECT 0.680 4340.400 58.820 4343.200 ;
      RECT 0.680 4351.280 58.820 4354.080 ;
      RECT 0.680 4362.160 58.820 4364.960 ;
      RECT 0.680 4373.040 58.820 4375.840 ;
      RECT 0.680 4383.920 58.820 4386.720 ;
      RECT 0.680 4394.800 58.820 4397.600 ;
      RECT 0.680 4405.680 58.820 4408.480 ;
      RECT 0.680 4416.560 58.820 4419.360 ;
      RECT 0.680 4427.440 58.820 4430.240 ;
      RECT 0.680 4438.320 58.820 4441.120 ;
      RECT 0.680 4449.200 58.820 4452.000 ;
      RECT 0.680 4460.080 58.820 4462.880 ;
      RECT 0.680 4470.960 58.820 4473.760 ;
      RECT 0.680 4481.840 58.820 4484.640 ;
      RECT 0.680 4492.720 58.820 4495.520 ;
      RECT 0.680 4503.600 58.820 4506.400 ;
      RECT 0.680 4514.480 58.820 4517.280 ;
      RECT 0.680 4525.360 58.820 4528.160 ;
      RECT 0.680 4536.240 58.820 4539.040 ;
      RECT 0.680 4547.120 58.820 4549.920 ;
      RECT 0.680 4558.000 58.820 4560.800 ;
      RECT 0.680 4568.880 58.820 4571.680 ;
      RECT 0.680 4579.760 58.820 4582.560 ;
      RECT 0.680 4590.640 58.820 4593.440 ;
      RECT 0.680 4601.520 58.820 4604.320 ;
      RECT 0.680 4612.400 58.820 4615.200 ;
      RECT 0.680 4623.280 58.820 4626.080 ;
      RECT 0.680 4634.160 58.820 4636.960 ;
      RECT 0.680 4645.040 58.820 4647.840 ;
      RECT 0.680 4655.920 58.820 4658.720 ;
      RECT 0.680 4666.800 58.820 4669.600 ;
      RECT 0.680 4677.680 58.820 4680.480 ;
      RECT 0.680 4688.560 58.820 4691.360 ;
      RECT 0.680 4699.440 58.820 4702.240 ;
      RECT 0.680 4710.320 58.820 4713.120 ;
      RECT 0.680 4721.200 58.820 4724.000 ;
      RECT 0.680 4732.080 58.820 4734.880 ;
      RECT 0.680 4742.960 58.820 4745.760 ;
      RECT 0.680 4753.840 58.820 4756.640 ;
      RECT 0.680 4764.720 58.820 4767.520 ;
      RECT 0.680 4775.600 58.820 4778.400 ;
      RECT 0.680 4786.480 58.820 4789.280 ;
      RECT 0.680 4797.360 58.820 4800.160 ;
      RECT 0.680 4808.240 58.820 4811.040 ;
      RECT 0.680 4819.120 58.820 4821.920 ;
      RECT 0.680 4830.000 58.820 4832.800 ;
      RECT 0.680 4840.880 58.820 4843.680 ;
      RECT 0.680 4851.760 58.820 4854.560 ;
      RECT 0.680 4862.640 58.820 4865.440 ;
      RECT 0.680 4873.520 58.820 4876.320 ;
      RECT 0.680 4884.400 58.820 4887.200 ;
      RECT 0.680 4895.280 58.820 4898.080 ;
      RECT 0.680 4906.160 58.820 4908.960 ;
      RECT 0.680 4917.040 58.820 4919.840 ;
      RECT 0.680 4927.920 58.820 4930.720 ;
      RECT 0.680 4938.800 58.820 4941.600 ;
      RECT 0.680 4949.680 58.820 4952.480 ;
      RECT 0.680 4960.560 58.820 4963.360 ;
      RECT 0.680 4971.440 58.820 4974.240 ;
      RECT 0.680 4982.320 58.820 4985.120 ;
      RECT 0.680 4993.200 58.820 4996.000 ;
      RECT 0.680 5004.080 58.820 5006.880 ;
      RECT 0.680 5014.960 58.820 5017.760 ;
      RECT 0.680 5025.840 58.820 5028.640 ;
      RECT 0.680 5036.720 58.820 5039.520 ;
      RECT 0.680 5047.600 58.820 5050.400 ;
      RECT 0.680 5058.480 58.820 5061.280 ;
      RECT 0.680 5069.360 58.820 5072.160 ;
      RECT 0.680 5080.240 58.820 5083.040 ;
      RECT 0.680 5091.120 58.820 5093.920 ;
      RECT 0.680 5102.000 58.820 5104.800 ;
      RECT 0.680 5112.880 58.820 5115.680 ;
      RECT 0.680 5123.760 58.820 5126.560 ;
      RECT 0.680 5134.640 58.820 5137.440 ;
      RECT 0.680 5145.520 58.820 5148.320 ;
      RECT 0.680 5156.400 58.820 5159.200 ;
      RECT 0.680 5167.280 58.820 5170.080 ;
      RECT 0.680 5178.160 58.820 5180.960 ;
      RECT 0.680 5189.040 58.820 5191.840 ;
      RECT 0.680 5199.920 58.820 5202.720 ;
      RECT 0.680 5210.800 58.820 5213.600 ;
      RECT 0.680 5221.680 58.820 5224.480 ;
      RECT 0.680 5232.560 58.820 5235.360 ;
      RECT 0.680 5243.440 58.820 5246.240 ;
      RECT 0.680 5254.320 58.820 5257.120 ;
      RECT 0.680 5265.200 58.820 5268.000 ;
      RECT 0.680 5276.080 58.820 5278.880 ;
      RECT 0.680 5286.960 58.820 5289.760 ;
      RECT 0.680 5297.840 58.820 5300.640 ;
      RECT 0.680 5308.720 58.820 5311.520 ;
      RECT 0.680 5319.600 58.820 5322.400 ;
      RECT 0.680 5330.480 58.820 5333.280 ;
      RECT 0.680 5341.360 58.820 5344.160 ;
      RECT 0.680 5352.240 58.820 5355.040 ;
      RECT 0.680 5363.120 58.820 5365.920 ;
      RECT 0.680 5374.000 58.820 5376.800 ;
      RECT 0.680 5384.880 58.820 5387.680 ;
      RECT 0.680 5395.760 58.820 5398.560 ;
      RECT 0.680 5406.640 58.820 5409.440 ;
      RECT 0.680 5417.520 58.820 5420.320 ;
      RECT 0.680 5428.400 58.820 5431.200 ;
      RECT 0.680 5439.280 58.820 5442.080 ;
      RECT 0.680 5450.160 58.820 5452.960 ;
      RECT 0.680 5461.040 58.820 5463.840 ;
      RECT 0.680 5471.920 58.820 5474.720 ;
      RECT 0.680 5482.800 58.820 5485.600 ;
      RECT 0.680 5493.680 58.820 5496.480 ;
      RECT 0.680 5504.560 58.820 5507.360 ;
      RECT 0.680 5515.440 58.820 5518.240 ;
      RECT 0.680 5526.320 58.820 5529.120 ;
      RECT 0.680 5537.200 58.820 5540.000 ;
      RECT 0.680 5548.080 58.820 5550.880 ;
      RECT 0.680 5558.960 58.820 5561.760 ;
      RECT 0.680 5569.840 58.820 5572.640 ;
      RECT 0.680 5580.720 58.820 5583.520 ;
      RECT 0.680 5591.600 58.820 5594.400 ;
      RECT 0.680 5602.480 58.820 5605.280 ;
      RECT 0.680 5613.360 58.820 5616.160 ;
      RECT 0.680 5624.240 58.820 5627.040 ;
      RECT 0.680 5635.120 58.820 5637.920 ;
      RECT 0.680 5646.000 58.820 5648.800 ;
      RECT 0.680 5656.880 58.820 5659.680 ;
      RECT 0.680 5667.760 58.820 5670.560 ;
      RECT 0.680 5678.640 58.820 5681.440 ;
      RECT 0.680 5689.520 58.820 5692.320 ;
      RECT 0.680 5700.400 58.820 5703.200 ;
      RECT 0.680 5711.280 58.820 5714.080 ;
      RECT 0.680 5722.160 58.820 5724.960 ;
      RECT 0.680 5733.040 58.820 5735.840 ;
      RECT 0.680 5743.920 58.820 5746.720 ;
      RECT 0.680 5754.800 58.820 5757.600 ;
      RECT 0.680 5765.680 58.820 5768.480 ;
      RECT 0.680 5776.560 58.820 5779.360 ;
      RECT 0.680 5787.440 58.820 5790.240 ;
      RECT 0.680 5798.320 58.820 5801.120 ;
      RECT 0.680 5809.200 58.820 5812.000 ;
      RECT 0.680 5820.080 58.820 5822.880 ;
      RECT 0.680 5830.960 58.820 5833.760 ;
      RECT 0.680 5841.840 58.820 5844.640 ;
      RECT 0.680 5852.720 58.820 5855.520 ;
      RECT 0.680 5863.600 58.820 5866.400 ;
      RECT 0.680 5874.480 58.820 5877.280 ;
      RECT 0.680 5885.360 58.820 5888.160 ;
      RECT 0.680 5896.240 58.820 5899.040 ;
      RECT 0.680 5907.120 58.820 5909.920 ;
      RECT 0.680 5918.000 58.820 5920.800 ;
      RECT 0.680 5928.880 58.820 5931.680 ;
      RECT 0.680 5939.760 58.820 5942.560 ;
      RECT 0.680 5950.640 58.820 5953.440 ;
      RECT 0.680 5961.520 58.820 5964.320 ;
      RECT 0.680 5972.400 58.820 5975.200 ;
      RECT 0.680 5983.280 58.820 5986.080 ;
      RECT 0.680 5994.160 58.820 5996.960 ;
      RECT 0.680 6005.040 58.820 6007.840 ;
      RECT 0.680 6015.920 58.820 6018.720 ;
      RECT 0.680 6026.800 58.820 6029.600 ;
      RECT 0.680 6037.680 58.820 6040.480 ;
      RECT 0.680 6048.560 58.820 6051.360 ;
      RECT 0.680 6059.440 58.820 6062.240 ;
      RECT 0.680 6070.320 58.820 6073.120 ;
      RECT 0.680 6081.200 58.820 6084.000 ;
      RECT 0.680 6092.080 58.820 6094.880 ;
      RECT 0.680 6102.960 58.820 6105.760 ;
      RECT 0.680 6113.840 58.820 6116.640 ;
      RECT 0.680 6124.720 58.820 6127.520 ;
      RECT 0.680 6135.600 58.820 6138.400 ;
      RECT 0.680 6146.480 58.820 6149.280 ;
      RECT 0.680 6157.360 58.820 6160.160 ;
      RECT 0.680 6168.240 58.820 6171.040 ;
      RECT 0.680 6179.120 58.820 6181.920 ;
      RECT 0.680 6190.000 58.820 6192.800 ;
      RECT 0.680 6200.880 58.820 6203.680 ;
      RECT 0.680 6211.760 58.820 6214.560 ;
      RECT 0.680 6222.640 58.820 6225.440 ;
      RECT 0.680 6233.520 58.820 6236.320 ;
      RECT 0.680 6244.400 58.820 6247.200 ;
      RECT 0.680 6255.280 58.820 6258.080 ;
      RECT 0.680 6266.160 58.820 6268.960 ;
      RECT 0.680 6277.040 58.820 6279.840 ;
      RECT 0.680 6287.920 58.820 6290.720 ;
      RECT 0.680 6298.800 58.820 6301.600 ;
      RECT 0.680 6309.680 58.820 6312.480 ;
      RECT 0.680 6320.560 58.820 6323.360 ;
      RECT 0.680 6331.440 58.820 6334.240 ;
      RECT 0.680 6342.320 58.820 6345.120 ;
      RECT 0.680 6353.200 58.820 6356.000 ;
      RECT 0.680 6364.080 58.820 6366.880 ;
      RECT 0.680 6374.960 58.820 6377.760 ;
      RECT 0.680 6385.840 58.820 6388.640 ;
      RECT 0.680 6396.720 58.820 6399.520 ;
      RECT 0.680 6407.600 58.820 6410.400 ;
      RECT 0.680 6418.480 58.820 6421.280 ;
      RECT 0.680 6429.360 58.820 6432.160 ;
      RECT 0.680 6440.240 58.820 6443.040 ;
      RECT 0.680 6451.120 58.820 6453.920 ;
      RECT 0.680 6462.000 58.820 6464.800 ;
      RECT 0.680 6472.880 58.820 6475.680 ;
      RECT 0.680 6483.760 58.820 6486.560 ;
      RECT 0.680 6494.640 58.820 6497.440 ;
      RECT 0.680 6505.520 58.820 6508.320 ;
      RECT 0.680 6516.400 58.820 6519.200 ;
      RECT 0.680 6527.280 58.820 6530.080 ;
      RECT 0.680 6538.160 58.820 6540.960 ;
      RECT 0.680 6549.040 58.820 6551.840 ;
      RECT 0.680 6559.920 58.820 6562.720 ;
      RECT 0.680 6570.800 58.820 6573.600 ;
      RECT 0.680 6581.680 58.820 6584.480 ;
      RECT 0.680 6592.560 58.820 6595.360 ;
      RECT 0.680 6603.440 58.820 6606.240 ;
      RECT 0.680 6614.320 58.820 6617.120 ;
      RECT 0.680 6625.200 58.820 6628.000 ;
      RECT 0.680 6636.080 58.820 6638.880 ;
      RECT 0.680 6646.960 58.820 6649.760 ;
      RECT 0.680 6657.840 58.820 6660.640 ;
      RECT 0.680 6668.720 58.820 6671.520 ;
      RECT 0.680 6679.600 58.820 6682.400 ;
      RECT 0.680 6690.480 58.820 6693.280 ;
      RECT 0.680 6701.360 58.820 6704.160 ;
      RECT 0.680 6712.240 58.820 6715.040 ;
      RECT 0.680 6723.120 58.820 6725.920 ;
      RECT 0.680 6734.000 58.820 6736.800 ;
      RECT 0.680 6744.880 58.820 6747.680 ;
      RECT 0.680 6755.760 58.820 6758.560 ;
      RECT 0.680 6766.640 58.820 6769.440 ;
      RECT 0.680 6777.520 58.820 6780.320 ;
      RECT 0.680 6788.400 58.820 6791.200 ;
      RECT 0.680 6799.280 58.820 6802.080 ;
      RECT 0.680 6810.160 58.820 6812.960 ;
      RECT 0.680 6821.040 58.820 6823.840 ;
      RECT 0.680 6831.920 58.820 6834.720 ;
      RECT 0.680 6842.800 58.820 6845.600 ;
      RECT 0.680 6853.680 58.820 6856.480 ;
      RECT 0.680 6864.560 58.820 6867.360 ;
      RECT 0.680 6875.440 58.820 6878.240 ;
      RECT 0.680 6886.320 58.820 6889.120 ;
      RECT 0.680 6897.200 58.820 6900.000 ;
      RECT 0.680 6908.080 58.820 6910.880 ;
      RECT 0.680 6918.960 58.820 6921.760 ;
      RECT 0.680 6929.840 58.820 6932.640 ;
      RECT 0.680 6940.720 58.820 6943.520 ;
      RECT 0.680 6951.600 58.820 6954.400 ;
      RECT 0.680 6962.480 58.820 6965.280 ;
      RECT 0.680 6973.360 58.820 6976.160 ;
      RECT 0.680 6984.240 58.820 6987.040 ;
      RECT 0.680 6995.120 58.820 6997.920 ;
      RECT 0.680 7006.000 58.820 7008.800 ;
      RECT 0.680 7016.880 58.820 7019.680 ;
      RECT 0.680 7027.760 58.820 7030.560 ;
      RECT 0.680 7038.640 58.820 7041.440 ;
      RECT 0.680 7049.520 58.820 7052.320 ;
      RECT 0.680 7060.400 58.820 7063.200 ;
      RECT 0.680 7071.280 58.820 7074.080 ;
      RECT 0.680 7082.160 58.820 7084.960 ;
      RECT 0.680 7093.040 58.820 7095.840 ;
      RECT 0.680 7103.920 58.820 7106.720 ;
      RECT 0.680 7114.800 58.820 7117.600 ;
      RECT 0.680 7125.680 58.820 7128.480 ;
      RECT 0.680 7136.560 58.820 7139.360 ;
      RECT 0.680 7147.440 58.820 7150.240 ;
      RECT 0.680 7158.320 58.820 7161.120 ;
      RECT 0.680 7169.200 58.820 7172.000 ;
      RECT 0.680 7180.080 58.820 7182.880 ;
      RECT 0.680 7190.960 58.820 7193.760 ;
      RECT 0.680 7201.840 58.820 7204.640 ;
      RECT 0.680 7212.720 58.820 7215.520 ;
      RECT 0.680 7223.600 58.820 7226.400 ;
      RECT 0.680 7234.480 58.820 7237.280 ;
      RECT 0.680 7245.360 58.820 7248.160 ;
      RECT 0.680 7256.240 58.820 7259.040 ;
      RECT 0.680 7267.120 58.820 7269.920 ;
      RECT 0.680 7278.000 58.820 7280.800 ;
      RECT 0.680 7288.880 58.820 7291.680 ;
      RECT 0.680 7299.760 58.820 7302.560 ;
      RECT 0.680 7310.640 58.820 7313.440 ;
      RECT 0.680 7321.520 58.820 7324.320 ;
      RECT 0.680 7332.400 58.820 7335.200 ;
      RECT 0.680 7343.280 58.820 7346.080 ;
      RECT 0.680 7354.160 58.820 7356.960 ;
      RECT 0.680 7365.040 58.820 7367.840 ;
      RECT 0.680 7375.920 58.820 7378.720 ;
      RECT 0.680 7386.800 58.820 7389.600 ;
      RECT 0.680 7397.680 58.820 7400.480 ;
      RECT 0.680 7408.560 58.820 7411.360 ;
      RECT 0.680 7419.440 58.820 7422.240 ;
      RECT 0.680 7430.320 58.820 7433.120 ;
      RECT 0.680 7441.200 58.820 7444.000 ;
      RECT 0.680 7452.080 58.820 7454.880 ;
      RECT 0.680 7462.960 58.820 7465.760 ;
      RECT 0.680 7473.840 58.820 7476.640 ;
      RECT 0.680 7484.720 58.820 7487.520 ;
      RECT 0.680 7495.600 58.820 7498.400 ;
      RECT 0.680 7506.480 58.820 7509.280 ;
      RECT 0.680 7517.360 58.820 7520.160 ;
      RECT 0.680 7528.240 58.820 7531.040 ;
      RECT 0.680 7539.120 58.820 7541.920 ;
      RECT 0.680 7550.000 58.820 7552.800 ;
      RECT 0.680 7560.880 58.820 7563.680 ;
      RECT 0.680 7571.760 58.820 7574.560 ;
      RECT 0.680 7582.640 58.820 7585.440 ;
      RECT 0.680 7593.520 58.820 7596.320 ;
      RECT 0.680 7604.400 58.820 7607.200 ;
      RECT 0.680 7615.280 58.820 7618.080 ;
      RECT 0.680 7626.160 58.820 7628.960 ;
      RECT 0.680 7637.040 58.820 7639.840 ;
      RECT 0.680 7647.920 58.820 7650.720 ;
      RECT 0.680 7658.800 58.820 7661.600 ;
      RECT 0.680 7669.680 58.820 7672.480 ;
      RECT 0.680 7680.560 58.820 7683.360 ;
      RECT 0.680 7691.440 58.820 7694.240 ;
      RECT 0.680 7702.320 58.820 7705.120 ;
      RECT 0.680 7713.200 58.820 7716.000 ;
      RECT 0.680 7724.080 58.820 7726.880 ;
      RECT 0.680 7734.960 58.820 7737.760 ;
      RECT 0.680 7745.840 58.820 7748.640 ;
      RECT 0.680 7756.720 58.820 7759.520 ;
      RECT 0.680 7767.600 58.820 7770.400 ;
      RECT 0.680 7778.480 58.820 7781.280 ;
      RECT 0.680 7789.360 58.820 7792.160 ;
      RECT 0.680 7800.240 58.820 7803.040 ;
      RECT 0.680 7811.120 58.820 7813.920 ;
      RECT 0.680 7822.000 58.820 7824.800 ;
      RECT 0.680 7832.880 58.820 7835.680 ;
      RECT 0.680 7843.760 58.820 7846.560 ;
      RECT 0.680 7854.640 58.820 7857.440 ;
      RECT 0.680 7865.520 58.820 7868.320 ;
      RECT 0.680 7876.400 58.820 7879.200 ;
      RECT 0.680 7887.280 58.820 7890.080 ;
      RECT 0.680 7898.160 58.820 7900.960 ;
      RECT 0.680 7909.040 58.820 7911.840 ;
      RECT 0.680 7919.920 58.820 7922.720 ;
      RECT 0.680 7930.800 58.820 7933.600 ;
      RECT 0.680 7941.680 58.820 7944.480 ;
      RECT 0.680 7952.560 58.820 7955.360 ;
      RECT 0.680 7963.440 58.820 7966.240 ;
      RECT 0.680 7974.320 58.820 7977.120 ;
      RECT 0.680 7985.200 58.820 7988.000 ;
      RECT 0.680 7996.080 58.820 7998.880 ;
      RECT 0.680 8006.960 58.820 8009.760 ;
      RECT 0.680 8017.840 58.820 8020.640 ;
      RECT 0.680 8028.720 58.820 8031.520 ;
      RECT 0.680 8039.600 58.820 8042.400 ;
      RECT 0.680 8050.480 58.820 8053.280 ;
      RECT 0.680 8061.360 58.820 8064.160 ;
      RECT 0.680 8072.240 58.820 8075.040 ;
      RECT 0.680 8083.120 58.820 8085.920 ;
      RECT 0.680 8094.000 58.820 8096.800 ;
      RECT 0.680 8104.880 58.820 8107.680 ;
      RECT 0.680 8115.760 58.820 8118.560 ;
      RECT 0.680 8126.640 58.820 8129.440 ;
      RECT 0.680 8137.520 58.820 8140.320 ;
      RECT 0.680 8148.400 58.820 8151.200 ;
      RECT 0.680 8159.280 58.820 8162.080 ;
      RECT 0.680 8170.160 58.820 8172.960 ;
      RECT 0.680 8181.040 58.820 8183.840 ;
      RECT 0.680 8191.920 58.820 8194.720 ;
      RECT 0.680 8202.800 58.820 8205.600 ;
      RECT 0.680 8213.680 58.820 8216.480 ;
      RECT 0.680 8224.560 58.820 8227.360 ;
      RECT 0.680 8235.440 58.820 8238.240 ;
      RECT 0.680 8246.320 58.820 8249.120 ;
      RECT 0.680 8257.200 58.820 8260.000 ;
      RECT 0.680 8268.080 58.820 8270.880 ;
      RECT 0.680 8278.960 58.820 8281.760 ;
      RECT 0.680 8289.840 58.820 8292.640 ;
      RECT 0.680 8300.720 58.820 8303.520 ;
      RECT 0.680 8311.600 58.820 8314.400 ;
      RECT 0.680 8322.480 58.820 8325.280 ;
      RECT 0.680 8333.360 58.820 8336.160 ;
      RECT 0.680 8344.240 58.820 8347.040 ;
      RECT 0.680 8355.120 58.820 8357.920 ;
      RECT 0.680 8366.000 58.820 8368.800 ;
      RECT 0.680 8376.880 58.820 8379.680 ;
      RECT 0.680 8387.760 58.820 8390.560 ;
      RECT 0.680 8398.640 58.820 8401.440 ;
      RECT 0.680 8409.520 58.820 8412.320 ;
      RECT 0.680 8420.400 58.820 8423.200 ;
      RECT 0.680 8431.280 58.820 8434.080 ;
      RECT 0.680 8442.160 58.820 8444.960 ;
      RECT 0.680 8453.040 58.820 8455.840 ;
      RECT 0.680 8463.920 58.820 8466.720 ;
      RECT 0.680 8474.800 58.820 8477.600 ;
      RECT 0.680 8485.680 58.820 8488.480 ;
      RECT 0.680 8496.560 58.820 8499.360 ;
      RECT 0.680 8507.440 58.820 8510.240 ;
      RECT 0.680 8518.320 58.820 8521.120 ;
      RECT 0.680 8529.200 58.820 8532.000 ;
      RECT 0.680 8540.080 58.820 8542.880 ;
      RECT 0.680 8550.960 58.820 8553.760 ;
      RECT 0.680 8561.840 58.820 8564.640 ;
      RECT 0.680 8572.720 58.820 8575.520 ;
      RECT 0.680 8583.600 58.820 8586.400 ;
      RECT 0.680 8594.480 58.820 8597.280 ;
      RECT 0.680 8605.360 58.820 8608.160 ;
      RECT 0.680 8616.240 58.820 8619.040 ;
      RECT 0.680 8627.120 58.820 8629.920 ;
      RECT 0.680 8638.000 58.820 8640.800 ;
      RECT 0.680 8648.880 58.820 8651.680 ;
      RECT 0.680 8659.760 58.820 8662.560 ;
      RECT 0.680 8670.640 58.820 8673.440 ;
      RECT 0.680 8681.520 58.820 8684.320 ;
      RECT 0.680 8692.400 58.820 8695.200 ;
      RECT 0.680 8703.280 58.820 8706.080 ;
      RECT 0.680 8714.160 58.820 8716.960 ;
      RECT 0.680 8725.040 58.820 8727.840 ;
      RECT 0.680 8735.920 58.820 8738.720 ;
      RECT 0.680 8746.800 58.820 8749.600 ;
      RECT 0.680 8757.680 58.820 8760.480 ;
      RECT 0.680 8768.560 58.820 8771.360 ;
      RECT 0.680 8779.440 58.820 8782.240 ;
      RECT 0.680 8790.320 58.820 8793.120 ;
      RECT 0.680 8801.200 58.820 8804.000 ;
      RECT 0.680 8812.080 58.820 8814.880 ;
      RECT 0.680 8822.960 58.820 8825.760 ;
      RECT 0.680 8833.840 58.820 8836.640 ;
      RECT 0.680 8844.720 58.820 8847.520 ;
      RECT 0.680 8855.600 58.820 8858.400 ;
      RECT 0.680 8866.480 58.820 8869.280 ;
      RECT 0.680 8877.360 58.820 8880.160 ;
      RECT 0.680 8888.240 58.820 8891.040 ;
      RECT 0.680 8899.120 58.820 8901.920 ;
      RECT 0.680 8910.000 58.820 8912.800 ;
      RECT 0.680 8920.880 58.820 8923.680 ;
      RECT 0.680 8931.760 58.820 8934.560 ;
      RECT 0.680 8942.640 58.820 8945.440 ;
      RECT 0.680 8953.520 58.820 8956.320 ;
      RECT 0.680 8964.400 58.820 8967.200 ;
      RECT 0.680 8975.280 58.820 8978.080 ;
      RECT 0.680 8986.160 58.820 8988.960 ;
      RECT 0.680 8997.040 58.820 8999.840 ;
      RECT 0.680 9007.920 58.820 9010.720 ;
      RECT 0.680 9018.800 58.820 9021.600 ;
      RECT 0.680 9029.680 58.820 9032.480 ;
      RECT 0.680 9040.560 58.820 9043.360 ;
      RECT 0.680 9051.440 58.820 9054.240 ;
      RECT 0.680 9062.320 58.820 9065.120 ;
      RECT 0.680 9073.200 58.820 9076.000 ;
      RECT 0.680 9084.080 58.820 9086.880 ;
      RECT 0.680 9094.960 58.820 9097.760 ;
      RECT 0.680 9105.840 58.820 9108.640 ;
      RECT 0.680 9116.720 58.820 9119.520 ;
      RECT 0.680 9127.600 58.820 9130.400 ;
      RECT 0.680 9138.480 58.820 9141.280 ;
      RECT 0.680 9149.360 58.820 9152.160 ;
      RECT 0.680 9160.240 58.820 9163.040 ;
      RECT 0.680 9171.120 58.820 9173.920 ;
      RECT 0.680 9182.000 58.820 9184.800 ;
      RECT 0.680 9192.880 58.820 9195.680 ;
      RECT 0.680 9203.760 58.820 9206.560 ;
      RECT 0.680 9214.640 58.820 9217.440 ;
      RECT 0.680 9225.520 58.820 9228.320 ;
      RECT 0.680 9236.400 58.820 9239.200 ;
      RECT 0.680 9247.280 58.820 9250.080 ;
      RECT 0.680 9258.160 58.820 9260.960 ;
      RECT 0.680 9269.040 58.820 9271.840 ;
      RECT 0.680 9279.920 58.820 9282.720 ;
      RECT 0.680 9290.800 58.820 9293.600 ;
      RECT 0.680 9301.680 58.820 9304.480 ;
      RECT 0.680 9312.560 58.820 9315.360 ;
      RECT 0.680 9323.440 58.820 9326.240 ;
      RECT 0.680 9334.320 58.820 9337.120 ;
      RECT 0.680 9345.200 58.820 9348.000 ;
      RECT 0.680 9356.080 58.820 9358.880 ;
      RECT 0.680 9366.960 58.820 9369.760 ;
      RECT 0.680 9377.840 58.820 9380.640 ;
      RECT 0.680 9388.720 58.820 9391.520 ;
      RECT 0.680 9399.600 58.820 9402.400 ;
      RECT 0.680 9410.480 58.820 9413.280 ;
      RECT 0.680 9421.360 58.820 9424.160 ;
      RECT 0.680 9432.240 58.820 9435.040 ;
      RECT 0.680 9443.120 58.820 9445.920 ;
      RECT 0.680 9454.000 58.820 9456.800 ;
    END
  END VSS
  PIN VDD
    DIRECTION INOUT ;
    USE POWER ;
    PORT
      LAYER met3 ;
      RECT 0.680 4.720 58.820 7.520 ;
      RECT 0.680 15.600 58.820 18.400 ;
      RECT 0.680 26.480 58.820 29.280 ;
      RECT 0.680 37.360 58.820 40.160 ;
      RECT 0.680 48.240 58.820 51.040 ;
      RECT 0.680 59.120 58.820 61.920 ;
      RECT 0.680 70.000 58.820 72.800 ;
      RECT 0.680 80.880 58.820 83.680 ;
      RECT 0.680 91.760 58.820 94.560 ;
      RECT 0.680 102.640 58.820 105.440 ;
      RECT 0.680 113.520 58.820 116.320 ;
      RECT 0.680 124.400 58.820 127.200 ;
      RECT 0.680 135.280 58.820 138.080 ;
      RECT 0.680 146.160 58.820 148.960 ;
      RECT 0.680 157.040 58.820 159.840 ;
      RECT 0.680 167.920 58.820 170.720 ;
      RECT 0.680 178.800 58.820 181.600 ;
      RECT 0.680 189.680 58.820 192.480 ;
      RECT 0.680 200.560 58.820 203.360 ;
      RECT 0.680 211.440 58.820 214.240 ;
      RECT 0.680 222.320 58.820 225.120 ;
      RECT 0.680 233.200 58.820 236.000 ;
      RECT 0.680 244.080 58.820 246.880 ;
      RECT 0.680 254.960 58.820 257.760 ;
      RECT 0.680 265.840 58.820 268.640 ;
      RECT 0.680 276.720 58.820 279.520 ;
      RECT 0.680 287.600 58.820 290.400 ;
      RECT 0.680 298.480 58.820 301.280 ;
      RECT 0.680 309.360 58.820 312.160 ;
      RECT 0.680 320.240 58.820 323.040 ;
      RECT 0.680 331.120 58.820 333.920 ;
      RECT 0.680 342.000 58.820 344.800 ;
      RECT 0.680 352.880 58.820 355.680 ;
      RECT 0.680 363.760 58.820 366.560 ;
      RECT 0.680 374.640 58.820 377.440 ;
      RECT 0.680 385.520 58.820 388.320 ;
      RECT 0.680 396.400 58.820 399.200 ;
      RECT 0.680 407.280 58.820 410.080 ;
      RECT 0.680 418.160 58.820 420.960 ;
      RECT 0.680 429.040 58.820 431.840 ;
      RECT 0.680 439.920 58.820 442.720 ;
      RECT 0.680 450.800 58.820 453.600 ;
      RECT 0.680 461.680 58.820 464.480 ;
      RECT 0.680 472.560 58.820 475.360 ;
      RECT 0.680 483.440 58.820 486.240 ;
      RECT 0.680 494.320 58.820 497.120 ;
      RECT 0.680 505.200 58.820 508.000 ;
      RECT 0.680 516.080 58.820 518.880 ;
      RECT 0.680 526.960 58.820 529.760 ;
      RECT 0.680 537.840 58.820 540.640 ;
      RECT 0.680 548.720 58.820 551.520 ;
      RECT 0.680 559.600 58.820 562.400 ;
      RECT 0.680 570.480 58.820 573.280 ;
      RECT 0.680 581.360 58.820 584.160 ;
      RECT 0.680 592.240 58.820 595.040 ;
      RECT 0.680 603.120 58.820 605.920 ;
      RECT 0.680 614.000 58.820 616.800 ;
      RECT 0.680 624.880 58.820 627.680 ;
      RECT 0.680 635.760 58.820 638.560 ;
      RECT 0.680 646.640 58.820 649.440 ;
      RECT 0.680 657.520 58.820 660.320 ;
      RECT 0.680 668.400 58.820 671.200 ;
      RECT 0.680 679.280 58.820 682.080 ;
      RECT 0.680 690.160 58.820 692.960 ;
      RECT 0.680 701.040 58.820 703.840 ;
      RECT 0.680 711.920 58.820 714.720 ;
      RECT 0.680 722.800 58.820 725.600 ;
      RECT 0.680 733.680 58.820 736.480 ;
      RECT 0.680 744.560 58.820 747.360 ;
      RECT 0.680 755.440 58.820 758.240 ;
      RECT 0.680 766.320 58.820 769.120 ;
      RECT 0.680 777.200 58.820 780.000 ;
      RECT 0.680 788.080 58.820 790.880 ;
      RECT 0.680 798.960 58.820 801.760 ;
      RECT 0.680 809.840 58.820 812.640 ;
      RECT 0.680 820.720 58.820 823.520 ;
      RECT 0.680 831.600 58.820 834.400 ;
      RECT 0.680 842.480 58.820 845.280 ;
      RECT 0.680 853.360 58.820 856.160 ;
      RECT 0.680 864.240 58.820 867.040 ;
      RECT 0.680 875.120 58.820 877.920 ;
      RECT 0.680 886.000 58.820 888.800 ;
      RECT 0.680 896.880 58.820 899.680 ;
      RECT 0.680 907.760 58.820 910.560 ;
      RECT 0.680 918.640 58.820 921.440 ;
      RECT 0.680 929.520 58.820 932.320 ;
      RECT 0.680 940.400 58.820 943.200 ;
      RECT 0.680 951.280 58.820 954.080 ;
      RECT 0.680 962.160 58.820 964.960 ;
      RECT 0.680 973.040 58.820 975.840 ;
      RECT 0.680 983.920 58.820 986.720 ;
      RECT 0.680 994.800 58.820 997.600 ;
      RECT 0.680 1005.680 58.820 1008.480 ;
      RECT 0.680 1016.560 58.820 1019.360 ;
      RECT 0.680 1027.440 58.820 1030.240 ;
      RECT 0.680 1038.320 58.820 1041.120 ;
      RECT 0.680 1049.200 58.820 1052.000 ;
      RECT 0.680 1060.080 58.820 1062.880 ;
      RECT 0.680 1070.960 58.820 1073.760 ;
      RECT 0.680 1081.840 58.820 1084.640 ;
      RECT 0.680 1092.720 58.820 1095.520 ;
      RECT 0.680 1103.600 58.820 1106.400 ;
      RECT 0.680 1114.480 58.820 1117.280 ;
      RECT 0.680 1125.360 58.820 1128.160 ;
      RECT 0.680 1136.240 58.820 1139.040 ;
      RECT 0.680 1147.120 58.820 1149.920 ;
      RECT 0.680 1158.000 58.820 1160.800 ;
      RECT 0.680 1168.880 58.820 1171.680 ;
      RECT 0.680 1179.760 58.820 1182.560 ;
      RECT 0.680 1190.640 58.820 1193.440 ;
      RECT 0.680 1201.520 58.820 1204.320 ;
      RECT 0.680 1212.400 58.820 1215.200 ;
      RECT 0.680 1223.280 58.820 1226.080 ;
      RECT 0.680 1234.160 58.820 1236.960 ;
      RECT 0.680 1245.040 58.820 1247.840 ;
      RECT 0.680 1255.920 58.820 1258.720 ;
      RECT 0.680 1266.800 58.820 1269.600 ;
      RECT 0.680 1277.680 58.820 1280.480 ;
      RECT 0.680 1288.560 58.820 1291.360 ;
      RECT 0.680 1299.440 58.820 1302.240 ;
      RECT 0.680 1310.320 58.820 1313.120 ;
      RECT 0.680 1321.200 58.820 1324.000 ;
      RECT 0.680 1332.080 58.820 1334.880 ;
      RECT 0.680 1342.960 58.820 1345.760 ;
      RECT 0.680 1353.840 58.820 1356.640 ;
      RECT 0.680 1364.720 58.820 1367.520 ;
      RECT 0.680 1375.600 58.820 1378.400 ;
      RECT 0.680 1386.480 58.820 1389.280 ;
      RECT 0.680 1397.360 58.820 1400.160 ;
      RECT 0.680 1408.240 58.820 1411.040 ;
      RECT 0.680 1419.120 58.820 1421.920 ;
      RECT 0.680 1430.000 58.820 1432.800 ;
      RECT 0.680 1440.880 58.820 1443.680 ;
      RECT 0.680 1451.760 58.820 1454.560 ;
      RECT 0.680 1462.640 58.820 1465.440 ;
      RECT 0.680 1473.520 58.820 1476.320 ;
      RECT 0.680 1484.400 58.820 1487.200 ;
      RECT 0.680 1495.280 58.820 1498.080 ;
      RECT 0.680 1506.160 58.820 1508.960 ;
      RECT 0.680 1517.040 58.820 1519.840 ;
      RECT 0.680 1527.920 58.820 1530.720 ;
      RECT 0.680 1538.800 58.820 1541.600 ;
      RECT 0.680 1549.680 58.820 1552.480 ;
      RECT 0.680 1560.560 58.820 1563.360 ;
      RECT 0.680 1571.440 58.820 1574.240 ;
      RECT 0.680 1582.320 58.820 1585.120 ;
      RECT 0.680 1593.200 58.820 1596.000 ;
      RECT 0.680 1604.080 58.820 1606.880 ;
      RECT 0.680 1614.960 58.820 1617.760 ;
      RECT 0.680 1625.840 58.820 1628.640 ;
      RECT 0.680 1636.720 58.820 1639.520 ;
      RECT 0.680 1647.600 58.820 1650.400 ;
      RECT 0.680 1658.480 58.820 1661.280 ;
      RECT 0.680 1669.360 58.820 1672.160 ;
      RECT 0.680 1680.240 58.820 1683.040 ;
      RECT 0.680 1691.120 58.820 1693.920 ;
      RECT 0.680 1702.000 58.820 1704.800 ;
      RECT 0.680 1712.880 58.820 1715.680 ;
      RECT 0.680 1723.760 58.820 1726.560 ;
      RECT 0.680 1734.640 58.820 1737.440 ;
      RECT 0.680 1745.520 58.820 1748.320 ;
      RECT 0.680 1756.400 58.820 1759.200 ;
      RECT 0.680 1767.280 58.820 1770.080 ;
      RECT 0.680 1778.160 58.820 1780.960 ;
      RECT 0.680 1789.040 58.820 1791.840 ;
      RECT 0.680 1799.920 58.820 1802.720 ;
      RECT 0.680 1810.800 58.820 1813.600 ;
      RECT 0.680 1821.680 58.820 1824.480 ;
      RECT 0.680 1832.560 58.820 1835.360 ;
      RECT 0.680 1843.440 58.820 1846.240 ;
      RECT 0.680 1854.320 58.820 1857.120 ;
      RECT 0.680 1865.200 58.820 1868.000 ;
      RECT 0.680 1876.080 58.820 1878.880 ;
      RECT 0.680 1886.960 58.820 1889.760 ;
      RECT 0.680 1897.840 58.820 1900.640 ;
      RECT 0.680 1908.720 58.820 1911.520 ;
      RECT 0.680 1919.600 58.820 1922.400 ;
      RECT 0.680 1930.480 58.820 1933.280 ;
      RECT 0.680 1941.360 58.820 1944.160 ;
      RECT 0.680 1952.240 58.820 1955.040 ;
      RECT 0.680 1963.120 58.820 1965.920 ;
      RECT 0.680 1974.000 58.820 1976.800 ;
      RECT 0.680 1984.880 58.820 1987.680 ;
      RECT 0.680 1995.760 58.820 1998.560 ;
      RECT 0.680 2006.640 58.820 2009.440 ;
      RECT 0.680 2017.520 58.820 2020.320 ;
      RECT 0.680 2028.400 58.820 2031.200 ;
      RECT 0.680 2039.280 58.820 2042.080 ;
      RECT 0.680 2050.160 58.820 2052.960 ;
      RECT 0.680 2061.040 58.820 2063.840 ;
      RECT 0.680 2071.920 58.820 2074.720 ;
      RECT 0.680 2082.800 58.820 2085.600 ;
      RECT 0.680 2093.680 58.820 2096.480 ;
      RECT 0.680 2104.560 58.820 2107.360 ;
      RECT 0.680 2115.440 58.820 2118.240 ;
      RECT 0.680 2126.320 58.820 2129.120 ;
      RECT 0.680 2137.200 58.820 2140.000 ;
      RECT 0.680 2148.080 58.820 2150.880 ;
      RECT 0.680 2158.960 58.820 2161.760 ;
      RECT 0.680 2169.840 58.820 2172.640 ;
      RECT 0.680 2180.720 58.820 2183.520 ;
      RECT 0.680 2191.600 58.820 2194.400 ;
      RECT 0.680 2202.480 58.820 2205.280 ;
      RECT 0.680 2213.360 58.820 2216.160 ;
      RECT 0.680 2224.240 58.820 2227.040 ;
      RECT 0.680 2235.120 58.820 2237.920 ;
      RECT 0.680 2246.000 58.820 2248.800 ;
      RECT 0.680 2256.880 58.820 2259.680 ;
      RECT 0.680 2267.760 58.820 2270.560 ;
      RECT 0.680 2278.640 58.820 2281.440 ;
      RECT 0.680 2289.520 58.820 2292.320 ;
      RECT 0.680 2300.400 58.820 2303.200 ;
      RECT 0.680 2311.280 58.820 2314.080 ;
      RECT 0.680 2322.160 58.820 2324.960 ;
      RECT 0.680 2333.040 58.820 2335.840 ;
      RECT 0.680 2343.920 58.820 2346.720 ;
      RECT 0.680 2354.800 58.820 2357.600 ;
      RECT 0.680 2365.680 58.820 2368.480 ;
      RECT 0.680 2376.560 58.820 2379.360 ;
      RECT 0.680 2387.440 58.820 2390.240 ;
      RECT 0.680 2398.320 58.820 2401.120 ;
      RECT 0.680 2409.200 58.820 2412.000 ;
      RECT 0.680 2420.080 58.820 2422.880 ;
      RECT 0.680 2430.960 58.820 2433.760 ;
      RECT 0.680 2441.840 58.820 2444.640 ;
      RECT 0.680 2452.720 58.820 2455.520 ;
      RECT 0.680 2463.600 58.820 2466.400 ;
      RECT 0.680 2474.480 58.820 2477.280 ;
      RECT 0.680 2485.360 58.820 2488.160 ;
      RECT 0.680 2496.240 58.820 2499.040 ;
      RECT 0.680 2507.120 58.820 2509.920 ;
      RECT 0.680 2518.000 58.820 2520.800 ;
      RECT 0.680 2528.880 58.820 2531.680 ;
      RECT 0.680 2539.760 58.820 2542.560 ;
      RECT 0.680 2550.640 58.820 2553.440 ;
      RECT 0.680 2561.520 58.820 2564.320 ;
      RECT 0.680 2572.400 58.820 2575.200 ;
      RECT 0.680 2583.280 58.820 2586.080 ;
      RECT 0.680 2594.160 58.820 2596.960 ;
      RECT 0.680 2605.040 58.820 2607.840 ;
      RECT 0.680 2615.920 58.820 2618.720 ;
      RECT 0.680 2626.800 58.820 2629.600 ;
      RECT 0.680 2637.680 58.820 2640.480 ;
      RECT 0.680 2648.560 58.820 2651.360 ;
      RECT 0.680 2659.440 58.820 2662.240 ;
      RECT 0.680 2670.320 58.820 2673.120 ;
      RECT 0.680 2681.200 58.820 2684.000 ;
      RECT 0.680 2692.080 58.820 2694.880 ;
      RECT 0.680 2702.960 58.820 2705.760 ;
      RECT 0.680 2713.840 58.820 2716.640 ;
      RECT 0.680 2724.720 58.820 2727.520 ;
      RECT 0.680 2735.600 58.820 2738.400 ;
      RECT 0.680 2746.480 58.820 2749.280 ;
      RECT 0.680 2757.360 58.820 2760.160 ;
      RECT 0.680 2768.240 58.820 2771.040 ;
      RECT 0.680 2779.120 58.820 2781.920 ;
      RECT 0.680 2790.000 58.820 2792.800 ;
      RECT 0.680 2800.880 58.820 2803.680 ;
      RECT 0.680 2811.760 58.820 2814.560 ;
      RECT 0.680 2822.640 58.820 2825.440 ;
      RECT 0.680 2833.520 58.820 2836.320 ;
      RECT 0.680 2844.400 58.820 2847.200 ;
      RECT 0.680 2855.280 58.820 2858.080 ;
      RECT 0.680 2866.160 58.820 2868.960 ;
      RECT 0.680 2877.040 58.820 2879.840 ;
      RECT 0.680 2887.920 58.820 2890.720 ;
      RECT 0.680 2898.800 58.820 2901.600 ;
      RECT 0.680 2909.680 58.820 2912.480 ;
      RECT 0.680 2920.560 58.820 2923.360 ;
      RECT 0.680 2931.440 58.820 2934.240 ;
      RECT 0.680 2942.320 58.820 2945.120 ;
      RECT 0.680 2953.200 58.820 2956.000 ;
      RECT 0.680 2964.080 58.820 2966.880 ;
      RECT 0.680 2974.960 58.820 2977.760 ;
      RECT 0.680 2985.840 58.820 2988.640 ;
      RECT 0.680 2996.720 58.820 2999.520 ;
      RECT 0.680 3007.600 58.820 3010.400 ;
      RECT 0.680 3018.480 58.820 3021.280 ;
      RECT 0.680 3029.360 58.820 3032.160 ;
      RECT 0.680 3040.240 58.820 3043.040 ;
      RECT 0.680 3051.120 58.820 3053.920 ;
      RECT 0.680 3062.000 58.820 3064.800 ;
      RECT 0.680 3072.880 58.820 3075.680 ;
      RECT 0.680 3083.760 58.820 3086.560 ;
      RECT 0.680 3094.640 58.820 3097.440 ;
      RECT 0.680 3105.520 58.820 3108.320 ;
      RECT 0.680 3116.400 58.820 3119.200 ;
      RECT 0.680 3127.280 58.820 3130.080 ;
      RECT 0.680 3138.160 58.820 3140.960 ;
      RECT 0.680 3149.040 58.820 3151.840 ;
      RECT 0.680 3159.920 58.820 3162.720 ;
      RECT 0.680 3170.800 58.820 3173.600 ;
      RECT 0.680 3181.680 58.820 3184.480 ;
      RECT 0.680 3192.560 58.820 3195.360 ;
      RECT 0.680 3203.440 58.820 3206.240 ;
      RECT 0.680 3214.320 58.820 3217.120 ;
      RECT 0.680 3225.200 58.820 3228.000 ;
      RECT 0.680 3236.080 58.820 3238.880 ;
      RECT 0.680 3246.960 58.820 3249.760 ;
      RECT 0.680 3257.840 58.820 3260.640 ;
      RECT 0.680 3268.720 58.820 3271.520 ;
      RECT 0.680 3279.600 58.820 3282.400 ;
      RECT 0.680 3290.480 58.820 3293.280 ;
      RECT 0.680 3301.360 58.820 3304.160 ;
      RECT 0.680 3312.240 58.820 3315.040 ;
      RECT 0.680 3323.120 58.820 3325.920 ;
      RECT 0.680 3334.000 58.820 3336.800 ;
      RECT 0.680 3344.880 58.820 3347.680 ;
      RECT 0.680 3355.760 58.820 3358.560 ;
      RECT 0.680 3366.640 58.820 3369.440 ;
      RECT 0.680 3377.520 58.820 3380.320 ;
      RECT 0.680 3388.400 58.820 3391.200 ;
      RECT 0.680 3399.280 58.820 3402.080 ;
      RECT 0.680 3410.160 58.820 3412.960 ;
      RECT 0.680 3421.040 58.820 3423.840 ;
      RECT 0.680 3431.920 58.820 3434.720 ;
      RECT 0.680 3442.800 58.820 3445.600 ;
      RECT 0.680 3453.680 58.820 3456.480 ;
      RECT 0.680 3464.560 58.820 3467.360 ;
      RECT 0.680 3475.440 58.820 3478.240 ;
      RECT 0.680 3486.320 58.820 3489.120 ;
      RECT 0.680 3497.200 58.820 3500.000 ;
      RECT 0.680 3508.080 58.820 3510.880 ;
      RECT 0.680 3518.960 58.820 3521.760 ;
      RECT 0.680 3529.840 58.820 3532.640 ;
      RECT 0.680 3540.720 58.820 3543.520 ;
      RECT 0.680 3551.600 58.820 3554.400 ;
      RECT 0.680 3562.480 58.820 3565.280 ;
      RECT 0.680 3573.360 58.820 3576.160 ;
      RECT 0.680 3584.240 58.820 3587.040 ;
      RECT 0.680 3595.120 58.820 3597.920 ;
      RECT 0.680 3606.000 58.820 3608.800 ;
      RECT 0.680 3616.880 58.820 3619.680 ;
      RECT 0.680 3627.760 58.820 3630.560 ;
      RECT 0.680 3638.640 58.820 3641.440 ;
      RECT 0.680 3649.520 58.820 3652.320 ;
      RECT 0.680 3660.400 58.820 3663.200 ;
      RECT 0.680 3671.280 58.820 3674.080 ;
      RECT 0.680 3682.160 58.820 3684.960 ;
      RECT 0.680 3693.040 58.820 3695.840 ;
      RECT 0.680 3703.920 58.820 3706.720 ;
      RECT 0.680 3714.800 58.820 3717.600 ;
      RECT 0.680 3725.680 58.820 3728.480 ;
      RECT 0.680 3736.560 58.820 3739.360 ;
      RECT 0.680 3747.440 58.820 3750.240 ;
      RECT 0.680 3758.320 58.820 3761.120 ;
      RECT 0.680 3769.200 58.820 3772.000 ;
      RECT 0.680 3780.080 58.820 3782.880 ;
      RECT 0.680 3790.960 58.820 3793.760 ;
      RECT 0.680 3801.840 58.820 3804.640 ;
      RECT 0.680 3812.720 58.820 3815.520 ;
      RECT 0.680 3823.600 58.820 3826.400 ;
      RECT 0.680 3834.480 58.820 3837.280 ;
      RECT 0.680 3845.360 58.820 3848.160 ;
      RECT 0.680 3856.240 58.820 3859.040 ;
      RECT 0.680 3867.120 58.820 3869.920 ;
      RECT 0.680 3878.000 58.820 3880.800 ;
      RECT 0.680 3888.880 58.820 3891.680 ;
      RECT 0.680 3899.760 58.820 3902.560 ;
      RECT 0.680 3910.640 58.820 3913.440 ;
      RECT 0.680 3921.520 58.820 3924.320 ;
      RECT 0.680 3932.400 58.820 3935.200 ;
      RECT 0.680 3943.280 58.820 3946.080 ;
      RECT 0.680 3954.160 58.820 3956.960 ;
      RECT 0.680 3965.040 58.820 3967.840 ;
      RECT 0.680 3975.920 58.820 3978.720 ;
      RECT 0.680 3986.800 58.820 3989.600 ;
      RECT 0.680 3997.680 58.820 4000.480 ;
      RECT 0.680 4008.560 58.820 4011.360 ;
      RECT 0.680 4019.440 58.820 4022.240 ;
      RECT 0.680 4030.320 58.820 4033.120 ;
      RECT 0.680 4041.200 58.820 4044.000 ;
      RECT 0.680 4052.080 58.820 4054.880 ;
      RECT 0.680 4062.960 58.820 4065.760 ;
      RECT 0.680 4073.840 58.820 4076.640 ;
      RECT 0.680 4084.720 58.820 4087.520 ;
      RECT 0.680 4095.600 58.820 4098.400 ;
      RECT 0.680 4106.480 58.820 4109.280 ;
      RECT 0.680 4117.360 58.820 4120.160 ;
      RECT 0.680 4128.240 58.820 4131.040 ;
      RECT 0.680 4139.120 58.820 4141.920 ;
      RECT 0.680 4150.000 58.820 4152.800 ;
      RECT 0.680 4160.880 58.820 4163.680 ;
      RECT 0.680 4171.760 58.820 4174.560 ;
      RECT 0.680 4182.640 58.820 4185.440 ;
      RECT 0.680 4193.520 58.820 4196.320 ;
      RECT 0.680 4204.400 58.820 4207.200 ;
      RECT 0.680 4215.280 58.820 4218.080 ;
      RECT 0.680 4226.160 58.820 4228.960 ;
      RECT 0.680 4237.040 58.820 4239.840 ;
      RECT 0.680 4247.920 58.820 4250.720 ;
      RECT 0.680 4258.800 58.820 4261.600 ;
      RECT 0.680 4269.680 58.820 4272.480 ;
      RECT 0.680 4280.560 58.820 4283.360 ;
      RECT 0.680 4291.440 58.820 4294.240 ;
      RECT 0.680 4302.320 58.820 4305.120 ;
      RECT 0.680 4313.200 58.820 4316.000 ;
      RECT 0.680 4324.080 58.820 4326.880 ;
      RECT 0.680 4334.960 58.820 4337.760 ;
      RECT 0.680 4345.840 58.820 4348.640 ;
      RECT 0.680 4356.720 58.820 4359.520 ;
      RECT 0.680 4367.600 58.820 4370.400 ;
      RECT 0.680 4378.480 58.820 4381.280 ;
      RECT 0.680 4389.360 58.820 4392.160 ;
      RECT 0.680 4400.240 58.820 4403.040 ;
      RECT 0.680 4411.120 58.820 4413.920 ;
      RECT 0.680 4422.000 58.820 4424.800 ;
      RECT 0.680 4432.880 58.820 4435.680 ;
      RECT 0.680 4443.760 58.820 4446.560 ;
      RECT 0.680 4454.640 58.820 4457.440 ;
      RECT 0.680 4465.520 58.820 4468.320 ;
      RECT 0.680 4476.400 58.820 4479.200 ;
      RECT 0.680 4487.280 58.820 4490.080 ;
      RECT 0.680 4498.160 58.820 4500.960 ;
      RECT 0.680 4509.040 58.820 4511.840 ;
      RECT 0.680 4519.920 58.820 4522.720 ;
      RECT 0.680 4530.800 58.820 4533.600 ;
      RECT 0.680 4541.680 58.820 4544.480 ;
      RECT 0.680 4552.560 58.820 4555.360 ;
      RECT 0.680 4563.440 58.820 4566.240 ;
      RECT 0.680 4574.320 58.820 4577.120 ;
      RECT 0.680 4585.200 58.820 4588.000 ;
      RECT 0.680 4596.080 58.820 4598.880 ;
      RECT 0.680 4606.960 58.820 4609.760 ;
      RECT 0.680 4617.840 58.820 4620.640 ;
      RECT 0.680 4628.720 58.820 4631.520 ;
      RECT 0.680 4639.600 58.820 4642.400 ;
      RECT 0.680 4650.480 58.820 4653.280 ;
      RECT 0.680 4661.360 58.820 4664.160 ;
      RECT 0.680 4672.240 58.820 4675.040 ;
      RECT 0.680 4683.120 58.820 4685.920 ;
      RECT 0.680 4694.000 58.820 4696.800 ;
      RECT 0.680 4704.880 58.820 4707.680 ;
      RECT 0.680 4715.760 58.820 4718.560 ;
      RECT 0.680 4726.640 58.820 4729.440 ;
      RECT 0.680 4737.520 58.820 4740.320 ;
      RECT 0.680 4748.400 58.820 4751.200 ;
      RECT 0.680 4759.280 58.820 4762.080 ;
      RECT 0.680 4770.160 58.820 4772.960 ;
      RECT 0.680 4781.040 58.820 4783.840 ;
      RECT 0.680 4791.920 58.820 4794.720 ;
      RECT 0.680 4802.800 58.820 4805.600 ;
      RECT 0.680 4813.680 58.820 4816.480 ;
      RECT 0.680 4824.560 58.820 4827.360 ;
      RECT 0.680 4835.440 58.820 4838.240 ;
      RECT 0.680 4846.320 58.820 4849.120 ;
      RECT 0.680 4857.200 58.820 4860.000 ;
      RECT 0.680 4868.080 58.820 4870.880 ;
      RECT 0.680 4878.960 58.820 4881.760 ;
      RECT 0.680 4889.840 58.820 4892.640 ;
      RECT 0.680 4900.720 58.820 4903.520 ;
      RECT 0.680 4911.600 58.820 4914.400 ;
      RECT 0.680 4922.480 58.820 4925.280 ;
      RECT 0.680 4933.360 58.820 4936.160 ;
      RECT 0.680 4944.240 58.820 4947.040 ;
      RECT 0.680 4955.120 58.820 4957.920 ;
      RECT 0.680 4966.000 58.820 4968.800 ;
      RECT 0.680 4976.880 58.820 4979.680 ;
      RECT 0.680 4987.760 58.820 4990.560 ;
      RECT 0.680 4998.640 58.820 5001.440 ;
      RECT 0.680 5009.520 58.820 5012.320 ;
      RECT 0.680 5020.400 58.820 5023.200 ;
      RECT 0.680 5031.280 58.820 5034.080 ;
      RECT 0.680 5042.160 58.820 5044.960 ;
      RECT 0.680 5053.040 58.820 5055.840 ;
      RECT 0.680 5063.920 58.820 5066.720 ;
      RECT 0.680 5074.800 58.820 5077.600 ;
      RECT 0.680 5085.680 58.820 5088.480 ;
      RECT 0.680 5096.560 58.820 5099.360 ;
      RECT 0.680 5107.440 58.820 5110.240 ;
      RECT 0.680 5118.320 58.820 5121.120 ;
      RECT 0.680 5129.200 58.820 5132.000 ;
      RECT 0.680 5140.080 58.820 5142.880 ;
      RECT 0.680 5150.960 58.820 5153.760 ;
      RECT 0.680 5161.840 58.820 5164.640 ;
      RECT 0.680 5172.720 58.820 5175.520 ;
      RECT 0.680 5183.600 58.820 5186.400 ;
      RECT 0.680 5194.480 58.820 5197.280 ;
      RECT 0.680 5205.360 58.820 5208.160 ;
      RECT 0.680 5216.240 58.820 5219.040 ;
      RECT 0.680 5227.120 58.820 5229.920 ;
      RECT 0.680 5238.000 58.820 5240.800 ;
      RECT 0.680 5248.880 58.820 5251.680 ;
      RECT 0.680 5259.760 58.820 5262.560 ;
      RECT 0.680 5270.640 58.820 5273.440 ;
      RECT 0.680 5281.520 58.820 5284.320 ;
      RECT 0.680 5292.400 58.820 5295.200 ;
      RECT 0.680 5303.280 58.820 5306.080 ;
      RECT 0.680 5314.160 58.820 5316.960 ;
      RECT 0.680 5325.040 58.820 5327.840 ;
      RECT 0.680 5335.920 58.820 5338.720 ;
      RECT 0.680 5346.800 58.820 5349.600 ;
      RECT 0.680 5357.680 58.820 5360.480 ;
      RECT 0.680 5368.560 58.820 5371.360 ;
      RECT 0.680 5379.440 58.820 5382.240 ;
      RECT 0.680 5390.320 58.820 5393.120 ;
      RECT 0.680 5401.200 58.820 5404.000 ;
      RECT 0.680 5412.080 58.820 5414.880 ;
      RECT 0.680 5422.960 58.820 5425.760 ;
      RECT 0.680 5433.840 58.820 5436.640 ;
      RECT 0.680 5444.720 58.820 5447.520 ;
      RECT 0.680 5455.600 58.820 5458.400 ;
      RECT 0.680 5466.480 58.820 5469.280 ;
      RECT 0.680 5477.360 58.820 5480.160 ;
      RECT 0.680 5488.240 58.820 5491.040 ;
      RECT 0.680 5499.120 58.820 5501.920 ;
      RECT 0.680 5510.000 58.820 5512.800 ;
      RECT 0.680 5520.880 58.820 5523.680 ;
      RECT 0.680 5531.760 58.820 5534.560 ;
      RECT 0.680 5542.640 58.820 5545.440 ;
      RECT 0.680 5553.520 58.820 5556.320 ;
      RECT 0.680 5564.400 58.820 5567.200 ;
      RECT 0.680 5575.280 58.820 5578.080 ;
      RECT 0.680 5586.160 58.820 5588.960 ;
      RECT 0.680 5597.040 58.820 5599.840 ;
      RECT 0.680 5607.920 58.820 5610.720 ;
      RECT 0.680 5618.800 58.820 5621.600 ;
      RECT 0.680 5629.680 58.820 5632.480 ;
      RECT 0.680 5640.560 58.820 5643.360 ;
      RECT 0.680 5651.440 58.820 5654.240 ;
      RECT 0.680 5662.320 58.820 5665.120 ;
      RECT 0.680 5673.200 58.820 5676.000 ;
      RECT 0.680 5684.080 58.820 5686.880 ;
      RECT 0.680 5694.960 58.820 5697.760 ;
      RECT 0.680 5705.840 58.820 5708.640 ;
      RECT 0.680 5716.720 58.820 5719.520 ;
      RECT 0.680 5727.600 58.820 5730.400 ;
      RECT 0.680 5738.480 58.820 5741.280 ;
      RECT 0.680 5749.360 58.820 5752.160 ;
      RECT 0.680 5760.240 58.820 5763.040 ;
      RECT 0.680 5771.120 58.820 5773.920 ;
      RECT 0.680 5782.000 58.820 5784.800 ;
      RECT 0.680 5792.880 58.820 5795.680 ;
      RECT 0.680 5803.760 58.820 5806.560 ;
      RECT 0.680 5814.640 58.820 5817.440 ;
      RECT 0.680 5825.520 58.820 5828.320 ;
      RECT 0.680 5836.400 58.820 5839.200 ;
      RECT 0.680 5847.280 58.820 5850.080 ;
      RECT 0.680 5858.160 58.820 5860.960 ;
      RECT 0.680 5869.040 58.820 5871.840 ;
      RECT 0.680 5879.920 58.820 5882.720 ;
      RECT 0.680 5890.800 58.820 5893.600 ;
      RECT 0.680 5901.680 58.820 5904.480 ;
      RECT 0.680 5912.560 58.820 5915.360 ;
      RECT 0.680 5923.440 58.820 5926.240 ;
      RECT 0.680 5934.320 58.820 5937.120 ;
      RECT 0.680 5945.200 58.820 5948.000 ;
      RECT 0.680 5956.080 58.820 5958.880 ;
      RECT 0.680 5966.960 58.820 5969.760 ;
      RECT 0.680 5977.840 58.820 5980.640 ;
      RECT 0.680 5988.720 58.820 5991.520 ;
      RECT 0.680 5999.600 58.820 6002.400 ;
      RECT 0.680 6010.480 58.820 6013.280 ;
      RECT 0.680 6021.360 58.820 6024.160 ;
      RECT 0.680 6032.240 58.820 6035.040 ;
      RECT 0.680 6043.120 58.820 6045.920 ;
      RECT 0.680 6054.000 58.820 6056.800 ;
      RECT 0.680 6064.880 58.820 6067.680 ;
      RECT 0.680 6075.760 58.820 6078.560 ;
      RECT 0.680 6086.640 58.820 6089.440 ;
      RECT 0.680 6097.520 58.820 6100.320 ;
      RECT 0.680 6108.400 58.820 6111.200 ;
      RECT 0.680 6119.280 58.820 6122.080 ;
      RECT 0.680 6130.160 58.820 6132.960 ;
      RECT 0.680 6141.040 58.820 6143.840 ;
      RECT 0.680 6151.920 58.820 6154.720 ;
      RECT 0.680 6162.800 58.820 6165.600 ;
      RECT 0.680 6173.680 58.820 6176.480 ;
      RECT 0.680 6184.560 58.820 6187.360 ;
      RECT 0.680 6195.440 58.820 6198.240 ;
      RECT 0.680 6206.320 58.820 6209.120 ;
      RECT 0.680 6217.200 58.820 6220.000 ;
      RECT 0.680 6228.080 58.820 6230.880 ;
      RECT 0.680 6238.960 58.820 6241.760 ;
      RECT 0.680 6249.840 58.820 6252.640 ;
      RECT 0.680 6260.720 58.820 6263.520 ;
      RECT 0.680 6271.600 58.820 6274.400 ;
      RECT 0.680 6282.480 58.820 6285.280 ;
      RECT 0.680 6293.360 58.820 6296.160 ;
      RECT 0.680 6304.240 58.820 6307.040 ;
      RECT 0.680 6315.120 58.820 6317.920 ;
      RECT 0.680 6326.000 58.820 6328.800 ;
      RECT 0.680 6336.880 58.820 6339.680 ;
      RECT 0.680 6347.760 58.820 6350.560 ;
      RECT 0.680 6358.640 58.820 6361.440 ;
      RECT 0.680 6369.520 58.820 6372.320 ;
      RECT 0.680 6380.400 58.820 6383.200 ;
      RECT 0.680 6391.280 58.820 6394.080 ;
      RECT 0.680 6402.160 58.820 6404.960 ;
      RECT 0.680 6413.040 58.820 6415.840 ;
      RECT 0.680 6423.920 58.820 6426.720 ;
      RECT 0.680 6434.800 58.820 6437.600 ;
      RECT 0.680 6445.680 58.820 6448.480 ;
      RECT 0.680 6456.560 58.820 6459.360 ;
      RECT 0.680 6467.440 58.820 6470.240 ;
      RECT 0.680 6478.320 58.820 6481.120 ;
      RECT 0.680 6489.200 58.820 6492.000 ;
      RECT 0.680 6500.080 58.820 6502.880 ;
      RECT 0.680 6510.960 58.820 6513.760 ;
      RECT 0.680 6521.840 58.820 6524.640 ;
      RECT 0.680 6532.720 58.820 6535.520 ;
      RECT 0.680 6543.600 58.820 6546.400 ;
      RECT 0.680 6554.480 58.820 6557.280 ;
      RECT 0.680 6565.360 58.820 6568.160 ;
      RECT 0.680 6576.240 58.820 6579.040 ;
      RECT 0.680 6587.120 58.820 6589.920 ;
      RECT 0.680 6598.000 58.820 6600.800 ;
      RECT 0.680 6608.880 58.820 6611.680 ;
      RECT 0.680 6619.760 58.820 6622.560 ;
      RECT 0.680 6630.640 58.820 6633.440 ;
      RECT 0.680 6641.520 58.820 6644.320 ;
      RECT 0.680 6652.400 58.820 6655.200 ;
      RECT 0.680 6663.280 58.820 6666.080 ;
      RECT 0.680 6674.160 58.820 6676.960 ;
      RECT 0.680 6685.040 58.820 6687.840 ;
      RECT 0.680 6695.920 58.820 6698.720 ;
      RECT 0.680 6706.800 58.820 6709.600 ;
      RECT 0.680 6717.680 58.820 6720.480 ;
      RECT 0.680 6728.560 58.820 6731.360 ;
      RECT 0.680 6739.440 58.820 6742.240 ;
      RECT 0.680 6750.320 58.820 6753.120 ;
      RECT 0.680 6761.200 58.820 6764.000 ;
      RECT 0.680 6772.080 58.820 6774.880 ;
      RECT 0.680 6782.960 58.820 6785.760 ;
      RECT 0.680 6793.840 58.820 6796.640 ;
      RECT 0.680 6804.720 58.820 6807.520 ;
      RECT 0.680 6815.600 58.820 6818.400 ;
      RECT 0.680 6826.480 58.820 6829.280 ;
      RECT 0.680 6837.360 58.820 6840.160 ;
      RECT 0.680 6848.240 58.820 6851.040 ;
      RECT 0.680 6859.120 58.820 6861.920 ;
      RECT 0.680 6870.000 58.820 6872.800 ;
      RECT 0.680 6880.880 58.820 6883.680 ;
      RECT 0.680 6891.760 58.820 6894.560 ;
      RECT 0.680 6902.640 58.820 6905.440 ;
      RECT 0.680 6913.520 58.820 6916.320 ;
      RECT 0.680 6924.400 58.820 6927.200 ;
      RECT 0.680 6935.280 58.820 6938.080 ;
      RECT 0.680 6946.160 58.820 6948.960 ;
      RECT 0.680 6957.040 58.820 6959.840 ;
      RECT 0.680 6967.920 58.820 6970.720 ;
      RECT 0.680 6978.800 58.820 6981.600 ;
      RECT 0.680 6989.680 58.820 6992.480 ;
      RECT 0.680 7000.560 58.820 7003.360 ;
      RECT 0.680 7011.440 58.820 7014.240 ;
      RECT 0.680 7022.320 58.820 7025.120 ;
      RECT 0.680 7033.200 58.820 7036.000 ;
      RECT 0.680 7044.080 58.820 7046.880 ;
      RECT 0.680 7054.960 58.820 7057.760 ;
      RECT 0.680 7065.840 58.820 7068.640 ;
      RECT 0.680 7076.720 58.820 7079.520 ;
      RECT 0.680 7087.600 58.820 7090.400 ;
      RECT 0.680 7098.480 58.820 7101.280 ;
      RECT 0.680 7109.360 58.820 7112.160 ;
      RECT 0.680 7120.240 58.820 7123.040 ;
      RECT 0.680 7131.120 58.820 7133.920 ;
      RECT 0.680 7142.000 58.820 7144.800 ;
      RECT 0.680 7152.880 58.820 7155.680 ;
      RECT 0.680 7163.760 58.820 7166.560 ;
      RECT 0.680 7174.640 58.820 7177.440 ;
      RECT 0.680 7185.520 58.820 7188.320 ;
      RECT 0.680 7196.400 58.820 7199.200 ;
      RECT 0.680 7207.280 58.820 7210.080 ;
      RECT 0.680 7218.160 58.820 7220.960 ;
      RECT 0.680 7229.040 58.820 7231.840 ;
      RECT 0.680 7239.920 58.820 7242.720 ;
      RECT 0.680 7250.800 58.820 7253.600 ;
      RECT 0.680 7261.680 58.820 7264.480 ;
      RECT 0.680 7272.560 58.820 7275.360 ;
      RECT 0.680 7283.440 58.820 7286.240 ;
      RECT 0.680 7294.320 58.820 7297.120 ;
      RECT 0.680 7305.200 58.820 7308.000 ;
      RECT 0.680 7316.080 58.820 7318.880 ;
      RECT 0.680 7326.960 58.820 7329.760 ;
      RECT 0.680 7337.840 58.820 7340.640 ;
      RECT 0.680 7348.720 58.820 7351.520 ;
      RECT 0.680 7359.600 58.820 7362.400 ;
      RECT 0.680 7370.480 58.820 7373.280 ;
      RECT 0.680 7381.360 58.820 7384.160 ;
      RECT 0.680 7392.240 58.820 7395.040 ;
      RECT 0.680 7403.120 58.820 7405.920 ;
      RECT 0.680 7414.000 58.820 7416.800 ;
      RECT 0.680 7424.880 58.820 7427.680 ;
      RECT 0.680 7435.760 58.820 7438.560 ;
      RECT 0.680 7446.640 58.820 7449.440 ;
      RECT 0.680 7457.520 58.820 7460.320 ;
      RECT 0.680 7468.400 58.820 7471.200 ;
      RECT 0.680 7479.280 58.820 7482.080 ;
      RECT 0.680 7490.160 58.820 7492.960 ;
      RECT 0.680 7501.040 58.820 7503.840 ;
      RECT 0.680 7511.920 58.820 7514.720 ;
      RECT 0.680 7522.800 58.820 7525.600 ;
      RECT 0.680 7533.680 58.820 7536.480 ;
      RECT 0.680 7544.560 58.820 7547.360 ;
      RECT 0.680 7555.440 58.820 7558.240 ;
      RECT 0.680 7566.320 58.820 7569.120 ;
      RECT 0.680 7577.200 58.820 7580.000 ;
      RECT 0.680 7588.080 58.820 7590.880 ;
      RECT 0.680 7598.960 58.820 7601.760 ;
      RECT 0.680 7609.840 58.820 7612.640 ;
      RECT 0.680 7620.720 58.820 7623.520 ;
      RECT 0.680 7631.600 58.820 7634.400 ;
      RECT 0.680 7642.480 58.820 7645.280 ;
      RECT 0.680 7653.360 58.820 7656.160 ;
      RECT 0.680 7664.240 58.820 7667.040 ;
      RECT 0.680 7675.120 58.820 7677.920 ;
      RECT 0.680 7686.000 58.820 7688.800 ;
      RECT 0.680 7696.880 58.820 7699.680 ;
      RECT 0.680 7707.760 58.820 7710.560 ;
      RECT 0.680 7718.640 58.820 7721.440 ;
      RECT 0.680 7729.520 58.820 7732.320 ;
      RECT 0.680 7740.400 58.820 7743.200 ;
      RECT 0.680 7751.280 58.820 7754.080 ;
      RECT 0.680 7762.160 58.820 7764.960 ;
      RECT 0.680 7773.040 58.820 7775.840 ;
      RECT 0.680 7783.920 58.820 7786.720 ;
      RECT 0.680 7794.800 58.820 7797.600 ;
      RECT 0.680 7805.680 58.820 7808.480 ;
      RECT 0.680 7816.560 58.820 7819.360 ;
      RECT 0.680 7827.440 58.820 7830.240 ;
      RECT 0.680 7838.320 58.820 7841.120 ;
      RECT 0.680 7849.200 58.820 7852.000 ;
      RECT 0.680 7860.080 58.820 7862.880 ;
      RECT 0.680 7870.960 58.820 7873.760 ;
      RECT 0.680 7881.840 58.820 7884.640 ;
      RECT 0.680 7892.720 58.820 7895.520 ;
      RECT 0.680 7903.600 58.820 7906.400 ;
      RECT 0.680 7914.480 58.820 7917.280 ;
      RECT 0.680 7925.360 58.820 7928.160 ;
      RECT 0.680 7936.240 58.820 7939.040 ;
      RECT 0.680 7947.120 58.820 7949.920 ;
      RECT 0.680 7958.000 58.820 7960.800 ;
      RECT 0.680 7968.880 58.820 7971.680 ;
      RECT 0.680 7979.760 58.820 7982.560 ;
      RECT 0.680 7990.640 58.820 7993.440 ;
      RECT 0.680 8001.520 58.820 8004.320 ;
      RECT 0.680 8012.400 58.820 8015.200 ;
      RECT 0.680 8023.280 58.820 8026.080 ;
      RECT 0.680 8034.160 58.820 8036.960 ;
      RECT 0.680 8045.040 58.820 8047.840 ;
      RECT 0.680 8055.920 58.820 8058.720 ;
      RECT 0.680 8066.800 58.820 8069.600 ;
      RECT 0.680 8077.680 58.820 8080.480 ;
      RECT 0.680 8088.560 58.820 8091.360 ;
      RECT 0.680 8099.440 58.820 8102.240 ;
      RECT 0.680 8110.320 58.820 8113.120 ;
      RECT 0.680 8121.200 58.820 8124.000 ;
      RECT 0.680 8132.080 58.820 8134.880 ;
      RECT 0.680 8142.960 58.820 8145.760 ;
      RECT 0.680 8153.840 58.820 8156.640 ;
      RECT 0.680 8164.720 58.820 8167.520 ;
      RECT 0.680 8175.600 58.820 8178.400 ;
      RECT 0.680 8186.480 58.820 8189.280 ;
      RECT 0.680 8197.360 58.820 8200.160 ;
      RECT 0.680 8208.240 58.820 8211.040 ;
      RECT 0.680 8219.120 58.820 8221.920 ;
      RECT 0.680 8230.000 58.820 8232.800 ;
      RECT 0.680 8240.880 58.820 8243.680 ;
      RECT 0.680 8251.760 58.820 8254.560 ;
      RECT 0.680 8262.640 58.820 8265.440 ;
      RECT 0.680 8273.520 58.820 8276.320 ;
      RECT 0.680 8284.400 58.820 8287.200 ;
      RECT 0.680 8295.280 58.820 8298.080 ;
      RECT 0.680 8306.160 58.820 8308.960 ;
      RECT 0.680 8317.040 58.820 8319.840 ;
      RECT 0.680 8327.920 58.820 8330.720 ;
      RECT 0.680 8338.800 58.820 8341.600 ;
      RECT 0.680 8349.680 58.820 8352.480 ;
      RECT 0.680 8360.560 58.820 8363.360 ;
      RECT 0.680 8371.440 58.820 8374.240 ;
      RECT 0.680 8382.320 58.820 8385.120 ;
      RECT 0.680 8393.200 58.820 8396.000 ;
      RECT 0.680 8404.080 58.820 8406.880 ;
      RECT 0.680 8414.960 58.820 8417.760 ;
      RECT 0.680 8425.840 58.820 8428.640 ;
      RECT 0.680 8436.720 58.820 8439.520 ;
      RECT 0.680 8447.600 58.820 8450.400 ;
      RECT 0.680 8458.480 58.820 8461.280 ;
      RECT 0.680 8469.360 58.820 8472.160 ;
      RECT 0.680 8480.240 58.820 8483.040 ;
      RECT 0.680 8491.120 58.820 8493.920 ;
      RECT 0.680 8502.000 58.820 8504.800 ;
      RECT 0.680 8512.880 58.820 8515.680 ;
      RECT 0.680 8523.760 58.820 8526.560 ;
      RECT 0.680 8534.640 58.820 8537.440 ;
      RECT 0.680 8545.520 58.820 8548.320 ;
      RECT 0.680 8556.400 58.820 8559.200 ;
      RECT 0.680 8567.280 58.820 8570.080 ;
      RECT 0.680 8578.160 58.820 8580.960 ;
      RECT 0.680 8589.040 58.820 8591.840 ;
      RECT 0.680 8599.920 58.820 8602.720 ;
      RECT 0.680 8610.800 58.820 8613.600 ;
      RECT 0.680 8621.680 58.820 8624.480 ;
      RECT 0.680 8632.560 58.820 8635.360 ;
      RECT 0.680 8643.440 58.820 8646.240 ;
      RECT 0.680 8654.320 58.820 8657.120 ;
      RECT 0.680 8665.200 58.820 8668.000 ;
      RECT 0.680 8676.080 58.820 8678.880 ;
      RECT 0.680 8686.960 58.820 8689.760 ;
      RECT 0.680 8697.840 58.820 8700.640 ;
      RECT 0.680 8708.720 58.820 8711.520 ;
      RECT 0.680 8719.600 58.820 8722.400 ;
      RECT 0.680 8730.480 58.820 8733.280 ;
      RECT 0.680 8741.360 58.820 8744.160 ;
      RECT 0.680 8752.240 58.820 8755.040 ;
      RECT 0.680 8763.120 58.820 8765.920 ;
      RECT 0.680 8774.000 58.820 8776.800 ;
      RECT 0.680 8784.880 58.820 8787.680 ;
      RECT 0.680 8795.760 58.820 8798.560 ;
      RECT 0.680 8806.640 58.820 8809.440 ;
      RECT 0.680 8817.520 58.820 8820.320 ;
      RECT 0.680 8828.400 58.820 8831.200 ;
      RECT 0.680 8839.280 58.820 8842.080 ;
      RECT 0.680 8850.160 58.820 8852.960 ;
      RECT 0.680 8861.040 58.820 8863.840 ;
      RECT 0.680 8871.920 58.820 8874.720 ;
      RECT 0.680 8882.800 58.820 8885.600 ;
      RECT 0.680 8893.680 58.820 8896.480 ;
      RECT 0.680 8904.560 58.820 8907.360 ;
      RECT 0.680 8915.440 58.820 8918.240 ;
      RECT 0.680 8926.320 58.820 8929.120 ;
      RECT 0.680 8937.200 58.820 8940.000 ;
      RECT 0.680 8948.080 58.820 8950.880 ;
      RECT 0.680 8958.960 58.820 8961.760 ;
      RECT 0.680 8969.840 58.820 8972.640 ;
      RECT 0.680 8980.720 58.820 8983.520 ;
      RECT 0.680 8991.600 58.820 8994.400 ;
      RECT 0.680 9002.480 58.820 9005.280 ;
      RECT 0.680 9013.360 58.820 9016.160 ;
      RECT 0.680 9024.240 58.820 9027.040 ;
      RECT 0.680 9035.120 58.820 9037.920 ;
      RECT 0.680 9046.000 58.820 9048.800 ;
      RECT 0.680 9056.880 58.820 9059.680 ;
      RECT 0.680 9067.760 58.820 9070.560 ;
      RECT 0.680 9078.640 58.820 9081.440 ;
      RECT 0.680 9089.520 58.820 9092.320 ;
      RECT 0.680 9100.400 58.820 9103.200 ;
      RECT 0.680 9111.280 58.820 9114.080 ;
      RECT 0.680 9122.160 58.820 9124.960 ;
      RECT 0.680 9133.040 58.820 9135.840 ;
      RECT 0.680 9143.920 58.820 9146.720 ;
      RECT 0.680 9154.800 58.820 9157.600 ;
      RECT 0.680 9165.680 58.820 9168.480 ;
      RECT 0.680 9176.560 58.820 9179.360 ;
      RECT 0.680 9187.440 58.820 9190.240 ;
      RECT 0.680 9198.320 58.820 9201.120 ;
      RECT 0.680 9209.200 58.820 9212.000 ;
      RECT 0.680 9220.080 58.820 9222.880 ;
      RECT 0.680 9230.960 58.820 9233.760 ;
      RECT 0.680 9241.840 58.820 9244.640 ;
      RECT 0.680 9252.720 58.820 9255.520 ;
      RECT 0.680 9263.600 58.820 9266.400 ;
      RECT 0.680 9274.480 58.820 9277.280 ;
      RECT 0.680 9285.360 58.820 9288.160 ;
      RECT 0.680 9296.240 58.820 9299.040 ;
      RECT 0.680 9307.120 58.820 9309.920 ;
      RECT 0.680 9318.000 58.820 9320.800 ;
      RECT 0.680 9328.880 58.820 9331.680 ;
      RECT 0.680 9339.760 58.820 9342.560 ;
      RECT 0.680 9350.640 58.820 9353.440 ;
      RECT 0.680 9361.520 58.820 9364.320 ;
      RECT 0.680 9372.400 58.820 9375.200 ;
      RECT 0.680 9383.280 58.820 9386.080 ;
      RECT 0.680 9394.160 58.820 9396.960 ;
      RECT 0.680 9405.040 58.820 9407.840 ;
      RECT 0.680 9415.920 58.820 9418.720 ;
      RECT 0.680 9426.800 58.820 9429.600 ;
      RECT 0.680 9437.680 58.820 9440.480 ;
      RECT 0.680 9448.560 58.820 9451.360 ;
      RECT 0.680 9459.440 58.820 9462.240 ;
    END
  END VDD
  OBS
    LAYER met1 ;
    RECT 0 0 59.500 9464.000 ;
    LAYER met2 ;
    RECT 0 0 59.500 9464.000 ;
  END
END fakeram_32x1024
END LIBRARY
